VERSION 5.8 ;
BUSBITCHARS "[]" ;
DIVIDERCHAR "/" ;
UNITS
    DATABASE MICRONS 1000 ;
END UNITS

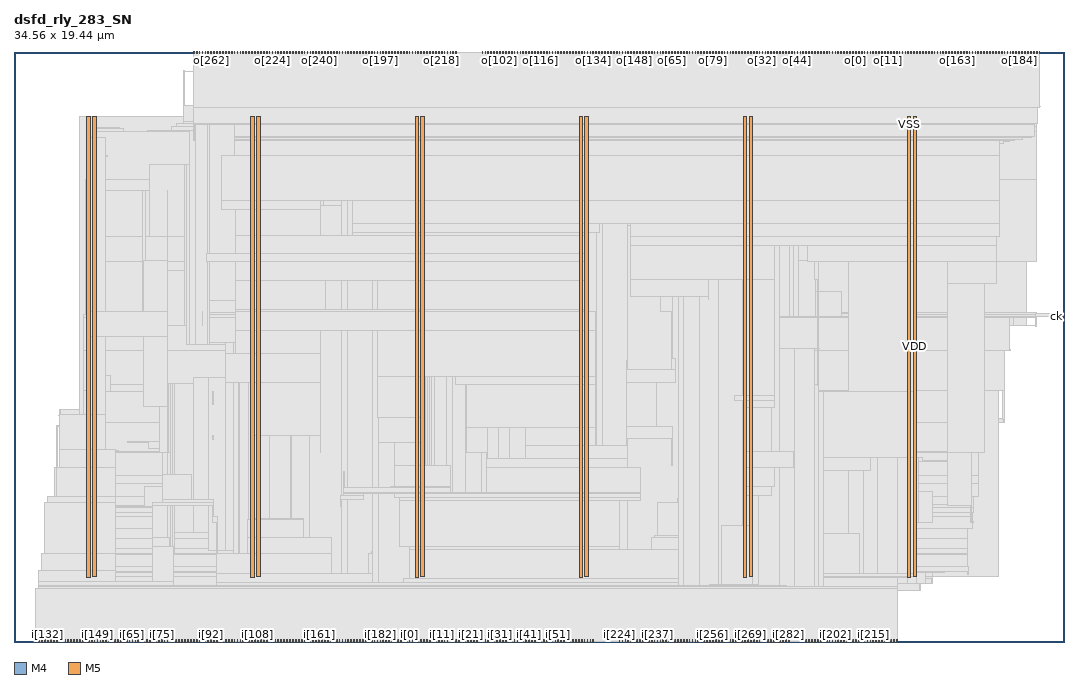
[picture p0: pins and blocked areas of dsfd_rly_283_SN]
MACRO dsfd_rly_283_SN
  FOREIGN dsfd_rly_283_SN 0 0 ;
  CLASS BLOCK ;
  SIZE 34.56 BY 19.44 ;
  PIN ck
    DIRECTION INPUT ;
    USE SIGNAL ;
    PORT
      LAYER M4 ;
        RECT  34.476 10.704 34.56 10.728 ;
    END
  END ck
  PIN i[0]
    DIRECTION INPUT ;
    USE SIGNAL ;
    PORT
      LAYER M5 ;
        RECT  13.008 0 13.032 0.084 ;
    END
  END i[0]
  PIN i[100]
    DIRECTION INPUT ;
    USE SIGNAL ;
    PORT
      LAYER M5 ;
        RECT  7.248 0 7.272 0.084 ;
    END
  END i[100]
  PIN i[101]
    DIRECTION INPUT ;
    USE SIGNAL ;
    PORT
      LAYER M5 ;
        RECT  7.344 0 7.368 0.084 ;
    END
  END i[101]
  PIN i[102]
    DIRECTION INPUT ;
    USE SIGNAL ;
    PORT
      LAYER M5 ;
        RECT  7.44 0 7.464 0.084 ;
    END
  END i[102]
  PIN i[103]
    DIRECTION INPUT ;
    USE SIGNAL ;
    PORT
      LAYER M5 ;
        RECT  7.536 0 7.56 0.084 ;
    END
  END i[103]
  PIN i[104]
    DIRECTION INPUT ;
    USE SIGNAL ;
    PORT
      LAYER M5 ;
        RECT  7.632 0 7.656 0.084 ;
    END
  END i[104]
  PIN i[105]
    DIRECTION INPUT ;
    USE SIGNAL ;
    PORT
      LAYER M5 ;
        RECT  7.728 0 7.752 0.084 ;
    END
  END i[105]
  PIN i[106]
    DIRECTION INPUT ;
    USE SIGNAL ;
    PORT
      LAYER M5 ;
        RECT  7.824 0 7.848 0.084 ;
    END
  END i[106]
  PIN i[107]
    DIRECTION INPUT ;
    USE SIGNAL ;
    PORT
      LAYER M5 ;
        RECT  7.92 0 7.944 0.084 ;
    END
  END i[107]
  PIN i[108]
    DIRECTION INPUT ;
    USE SIGNAL ;
    PORT
      LAYER M5 ;
        RECT  8.016 0 8.04 0.084 ;
    END
  END i[108]
  PIN i[109]
    DIRECTION INPUT ;
    USE SIGNAL ;
    PORT
      LAYER M5 ;
        RECT  8.112 0 8.136 0.084 ;
    END
  END i[109]
  PIN i[10]
    DIRECTION INPUT ;
    USE SIGNAL ;
    PORT
      LAYER M5 ;
        RECT  13.968 0 13.992 0.084 ;
    END
  END i[10]
  PIN i[110]
    DIRECTION INPUT ;
    USE SIGNAL ;
    PORT
      LAYER M5 ;
        RECT  8.208 0 8.232 0.084 ;
    END
  END i[110]
  PIN i[111]
    DIRECTION INPUT ;
    USE SIGNAL ;
    PORT
      LAYER M5 ;
        RECT  8.304 0 8.328 0.084 ;
    END
  END i[111]
  PIN i[112]
    DIRECTION INPUT ;
    USE SIGNAL ;
    PORT
      LAYER M5 ;
        RECT  8.4 0 8.424 0.084 ;
    END
  END i[112]
  PIN i[113]
    DIRECTION INPUT ;
    USE SIGNAL ;
    PORT
      LAYER M5 ;
        RECT  8.496 0 8.52 0.084 ;
    END
  END i[113]
  PIN i[114]
    DIRECTION INPUT ;
    USE SIGNAL ;
    PORT
      LAYER M5 ;
        RECT  8.592 0 8.616 0.084 ;
    END
  END i[114]
  PIN i[115]
    DIRECTION INPUT ;
    USE SIGNAL ;
    PORT
      LAYER M5 ;
        RECT  8.688 0 8.712 0.084 ;
    END
  END i[115]
  PIN i[116]
    DIRECTION INPUT ;
    USE SIGNAL ;
    PORT
      LAYER M5 ;
        RECT  8.784 0 8.808 0.084 ;
    END
  END i[116]
  PIN i[117]
    DIRECTION INPUT ;
    USE SIGNAL ;
    PORT
      LAYER M5 ;
        RECT  8.88 0 8.904 0.084 ;
    END
  END i[117]
  PIN i[118]
    DIRECTION INPUT ;
    USE SIGNAL ;
    PORT
      LAYER M5 ;
        RECT  8.976 0 9 0.084 ;
    END
  END i[118]
  PIN i[119]
    DIRECTION INPUT ;
    USE SIGNAL ;
    PORT
      LAYER M5 ;
        RECT  9.072 0 9.096 0.084 ;
    END
  END i[119]
  PIN i[11]
    DIRECTION INPUT ;
    USE SIGNAL ;
    PORT
      LAYER M5 ;
        RECT  14.064 0 14.088 0.084 ;
    END
  END i[11]
  PIN i[120]
    DIRECTION INPUT ;
    USE SIGNAL ;
    PORT
      LAYER M5 ;
        RECT  9.168 0 9.192 0.084 ;
    END
  END i[120]
  PIN i[121]
    DIRECTION INPUT ;
    USE SIGNAL ;
    PORT
      LAYER M5 ;
        RECT  9.264 0 9.288 0.084 ;
    END
  END i[121]
  PIN i[122]
    DIRECTION INPUT ;
    USE SIGNAL ;
    PORT
      LAYER M5 ;
        RECT  9.36 0 9.384 0.084 ;
    END
  END i[122]
  PIN i[123]
    DIRECTION INPUT ;
    USE SIGNAL ;
    PORT
      LAYER M5 ;
        RECT  9.456 0 9.48 0.084 ;
    END
  END i[123]
  PIN i[124]
    DIRECTION INPUT ;
    USE SIGNAL ;
    PORT
      LAYER M5 ;
        RECT  9.552 0 9.576 0.084 ;
    END
  END i[124]
  PIN i[125]
    DIRECTION INPUT ;
    USE SIGNAL ;
    PORT
      LAYER M5 ;
        RECT  9.648 0 9.672 0.084 ;
    END
  END i[125]
  PIN i[126]
    DIRECTION INPUT ;
    USE SIGNAL ;
    PORT
      LAYER M5 ;
        RECT  9.744 0 9.768 0.084 ;
    END
  END i[126]
  PIN i[127]
    DIRECTION INPUT ;
    USE SIGNAL ;
    PORT
      LAYER M5 ;
        RECT  9.84 0 9.864 0.084 ;
    END
  END i[127]
  PIN i[128]
    DIRECTION INPUT ;
    USE SIGNAL ;
    PORT
      LAYER M5 ;
        RECT  0.72 0 0.744 0.084 ;
    END
  END i[128]
  PIN i[129]
    DIRECTION INPUT ;
    USE SIGNAL ;
    PORT
      LAYER M5 ;
        RECT  0.816 0 0.84 0.084 ;
    END
  END i[129]
  PIN i[12]
    DIRECTION INPUT ;
    USE SIGNAL ;
    PORT
      LAYER M5 ;
        RECT  14.16 0 14.184 0.084 ;
    END
  END i[12]
  PIN i[130]
    DIRECTION INPUT ;
    USE SIGNAL ;
    PORT
      LAYER M5 ;
        RECT  0.912 0 0.936 0.084 ;
    END
  END i[130]
  PIN i[131]
    DIRECTION INPUT ;
    USE SIGNAL ;
    PORT
      LAYER M5 ;
        RECT  1.008 0 1.032 0.084 ;
    END
  END i[131]
  PIN i[132]
    DIRECTION INPUT ;
    USE SIGNAL ;
    PORT
      LAYER M5 ;
        RECT  1.104 0 1.128 0.084 ;
    END
  END i[132]
  PIN i[133]
    DIRECTION INPUT ;
    USE SIGNAL ;
    PORT
      LAYER M5 ;
        RECT  1.2 0 1.224 0.084 ;
    END
  END i[133]
  PIN i[134]
    DIRECTION INPUT ;
    USE SIGNAL ;
    PORT
      LAYER M5 ;
        RECT  1.296 0 1.32 0.084 ;
    END
  END i[134]
  PIN i[135]
    DIRECTION INPUT ;
    USE SIGNAL ;
    PORT
      LAYER M5 ;
        RECT  1.392 0 1.416 0.084 ;
    END
  END i[135]
  PIN i[136]
    DIRECTION INPUT ;
    USE SIGNAL ;
    PORT
      LAYER M5 ;
        RECT  1.488 0 1.512 0.084 ;
    END
  END i[136]
  PIN i[137]
    DIRECTION INPUT ;
    USE SIGNAL ;
    PORT
      LAYER M5 ;
        RECT  1.584 0 1.608 0.084 ;
    END
  END i[137]
  PIN i[138]
    DIRECTION INPUT ;
    USE SIGNAL ;
    PORT
      LAYER M5 ;
        RECT  1.68 0 1.704 0.084 ;
    END
  END i[138]
  PIN i[139]
    DIRECTION INPUT ;
    USE SIGNAL ;
    PORT
      LAYER M5 ;
        RECT  1.776 0 1.8 0.084 ;
    END
  END i[139]
  PIN i[13]
    DIRECTION INPUT ;
    USE SIGNAL ;
    PORT
      LAYER M5 ;
        RECT  14.256 0 14.28 0.084 ;
    END
  END i[13]
  PIN i[140]
    DIRECTION INPUT ;
    USE SIGNAL ;
    PORT
      LAYER M5 ;
        RECT  1.872 0 1.896 0.084 ;
    END
  END i[140]
  PIN i[141]
    DIRECTION INPUT ;
    USE SIGNAL ;
    PORT
      LAYER M5 ;
        RECT  1.968 0 1.992 0.084 ;
    END
  END i[141]
  PIN i[142]
    DIRECTION INPUT ;
    USE SIGNAL ;
    PORT
      LAYER M5 ;
        RECT  2.064 0 2.088 0.084 ;
    END
  END i[142]
  PIN i[143]
    DIRECTION INPUT ;
    USE SIGNAL ;
    PORT
      LAYER M5 ;
        RECT  2.16 0 2.184 0.084 ;
    END
  END i[143]
  PIN i[144]
    DIRECTION INPUT ;
    USE SIGNAL ;
    PORT
      LAYER M5 ;
        RECT  2.256 0 2.28 0.084 ;
    END
  END i[144]
  PIN i[145]
    DIRECTION INPUT ;
    USE SIGNAL ;
    PORT
      LAYER M5 ;
        RECT  2.352 0 2.376 0.084 ;
    END
  END i[145]
  PIN i[146]
    DIRECTION INPUT ;
    USE SIGNAL ;
    PORT
      LAYER M5 ;
        RECT  2.448 0 2.472 0.084 ;
    END
  END i[146]
  PIN i[147]
    DIRECTION INPUT ;
    USE SIGNAL ;
    PORT
      LAYER M5 ;
        RECT  2.544 0 2.568 0.084 ;
    END
  END i[147]
  PIN i[148]
    DIRECTION INPUT ;
    USE SIGNAL ;
    PORT
      LAYER M5 ;
        RECT  2.64 0 2.664 0.084 ;
    END
  END i[148]
  PIN i[149]
    DIRECTION INPUT ;
    USE SIGNAL ;
    PORT
      LAYER M5 ;
        RECT  2.736 0 2.76 0.084 ;
    END
  END i[149]
  PIN i[14]
    DIRECTION INPUT ;
    USE SIGNAL ;
    PORT
      LAYER M5 ;
        RECT  14.352 0 14.376 0.084 ;
    END
  END i[14]
  PIN i[150]
    DIRECTION INPUT ;
    USE SIGNAL ;
    PORT
      LAYER M5 ;
        RECT  2.832 0 2.856 0.084 ;
    END
  END i[150]
  PIN i[151]
    DIRECTION INPUT ;
    USE SIGNAL ;
    PORT
      LAYER M5 ;
        RECT  2.928 0 2.952 0.084 ;
    END
  END i[151]
  PIN i[152]
    DIRECTION INPUT ;
    USE SIGNAL ;
    PORT
      LAYER M5 ;
        RECT  3.024 0 3.048 0.084 ;
    END
  END i[152]
  PIN i[153]
    DIRECTION INPUT ;
    USE SIGNAL ;
    PORT
      LAYER M5 ;
        RECT  3.12 0 3.144 0.084 ;
    END
  END i[153]
  PIN i[154]
    DIRECTION INPUT ;
    USE SIGNAL ;
    PORT
      LAYER M5 ;
        RECT  3.216 0 3.24 0.084 ;
    END
  END i[154]
  PIN i[155]
    DIRECTION INPUT ;
    USE SIGNAL ;
    PORT
      LAYER M5 ;
        RECT  3.312 0 3.336 0.084 ;
    END
  END i[155]
  PIN i[156]
    DIRECTION INPUT ;
    USE SIGNAL ;
    PORT
      LAYER M5 ;
        RECT  3.408 0 3.432 0.084 ;
    END
  END i[156]
  PIN i[157]
    DIRECTION INPUT ;
    USE SIGNAL ;
    PORT
      LAYER M5 ;
        RECT  3.504 0 3.528 0.084 ;
    END
  END i[157]
  PIN i[158]
    DIRECTION INPUT ;
    USE SIGNAL ;
    PORT
      LAYER M5 ;
        RECT  3.6 0 3.624 0.084 ;
    END
  END i[158]
  PIN i[159]
    DIRECTION INPUT ;
    USE SIGNAL ;
    PORT
      LAYER M5 ;
        RECT  3.696 0 3.72 0.084 ;
    END
  END i[159]
  PIN i[15]
    DIRECTION INPUT ;
    USE SIGNAL ;
    PORT
      LAYER M5 ;
        RECT  14.448 0 14.472 0.084 ;
    END
  END i[15]
  PIN i[160]
    DIRECTION INPUT ;
    USE SIGNAL ;
    PORT
      LAYER M5 ;
        RECT  9.936 0 9.96 0.084 ;
    END
  END i[160]
  PIN i[161]
    DIRECTION INPUT ;
    USE SIGNAL ;
    PORT
      LAYER M5 ;
        RECT  10.032 0 10.056 0.084 ;
    END
  END i[161]
  PIN i[162]
    DIRECTION INPUT ;
    USE SIGNAL ;
    PORT
      LAYER M5 ;
        RECT  10.128 0 10.152 0.084 ;
    END
  END i[162]
  PIN i[163]
    DIRECTION INPUT ;
    USE SIGNAL ;
    PORT
      LAYER M5 ;
        RECT  10.224 0 10.248 0.084 ;
    END
  END i[163]
  PIN i[164]
    DIRECTION INPUT ;
    USE SIGNAL ;
    PORT
      LAYER M5 ;
        RECT  10.32 0 10.344 0.084 ;
    END
  END i[164]
  PIN i[165]
    DIRECTION INPUT ;
    USE SIGNAL ;
    PORT
      LAYER M5 ;
        RECT  10.416 0 10.44 0.084 ;
    END
  END i[165]
  PIN i[166]
    DIRECTION INPUT ;
    USE SIGNAL ;
    PORT
      LAYER M5 ;
        RECT  10.512 0 10.536 0.084 ;
    END
  END i[166]
  PIN i[167]
    DIRECTION INPUT ;
    USE SIGNAL ;
    PORT
      LAYER M5 ;
        RECT  10.608 0 10.632 0.084 ;
    END
  END i[167]
  PIN i[168]
    DIRECTION INPUT ;
    USE SIGNAL ;
    PORT
      LAYER M5 ;
        RECT  10.704 0 10.728 0.084 ;
    END
  END i[168]
  PIN i[169]
    DIRECTION INPUT ;
    USE SIGNAL ;
    PORT
      LAYER M5 ;
        RECT  10.8 0 10.824 0.084 ;
    END
  END i[169]
  PIN i[16]
    DIRECTION INPUT ;
    USE SIGNAL ;
    PORT
      LAYER M5 ;
        RECT  14.544 0 14.568 0.084 ;
    END
  END i[16]
  PIN i[170]
    DIRECTION INPUT ;
    USE SIGNAL ;
    PORT
      LAYER M5 ;
        RECT  10.896 0 10.92 0.084 ;
    END
  END i[170]
  PIN i[171]
    DIRECTION INPUT ;
    USE SIGNAL ;
    PORT
      LAYER M5 ;
        RECT  10.992 0 11.016 0.084 ;
    END
  END i[171]
  PIN i[172]
    DIRECTION INPUT ;
    USE SIGNAL ;
    PORT
      LAYER M5 ;
        RECT  11.088 0 11.112 0.084 ;
    END
  END i[172]
  PIN i[173]
    DIRECTION INPUT ;
    USE SIGNAL ;
    PORT
      LAYER M5 ;
        RECT  11.184 0 11.208 0.084 ;
    END
  END i[173]
  PIN i[174]
    DIRECTION INPUT ;
    USE SIGNAL ;
    PORT
      LAYER M5 ;
        RECT  11.28 0 11.304 0.084 ;
    END
  END i[174]
  PIN i[175]
    DIRECTION INPUT ;
    USE SIGNAL ;
    PORT
      LAYER M5 ;
        RECT  11.376 0 11.4 0.084 ;
    END
  END i[175]
  PIN i[176]
    DIRECTION INPUT ;
    USE SIGNAL ;
    PORT
      LAYER M5 ;
        RECT  11.472 0 11.496 0.084 ;
    END
  END i[176]
  PIN i[177]
    DIRECTION INPUT ;
    USE SIGNAL ;
    PORT
      LAYER M5 ;
        RECT  11.568 0 11.592 0.084 ;
    END
  END i[177]
  PIN i[178]
    DIRECTION INPUT ;
    USE SIGNAL ;
    PORT
      LAYER M5 ;
        RECT  11.664 0 11.688 0.084 ;
    END
  END i[178]
  PIN i[179]
    DIRECTION INPUT ;
    USE SIGNAL ;
    PORT
      LAYER M5 ;
        RECT  11.76 0 11.784 0.084 ;
    END
  END i[179]
  PIN i[17]
    DIRECTION INPUT ;
    USE SIGNAL ;
    PORT
      LAYER M5 ;
        RECT  14.64 0 14.664 0.084 ;
    END
  END i[17]
  PIN i[180]
    DIRECTION INPUT ;
    USE SIGNAL ;
    PORT
      LAYER M5 ;
        RECT  11.856 0 11.88 0.084 ;
    END
  END i[180]
  PIN i[181]
    DIRECTION INPUT ;
    USE SIGNAL ;
    PORT
      LAYER M5 ;
        RECT  11.952 0 11.976 0.084 ;
    END
  END i[181]
  PIN i[182]
    DIRECTION INPUT ;
    USE SIGNAL ;
    PORT
      LAYER M5 ;
        RECT  12.048 0 12.072 0.084 ;
    END
  END i[182]
  PIN i[183]
    DIRECTION INPUT ;
    USE SIGNAL ;
    PORT
      LAYER M5 ;
        RECT  12.144 0 12.168 0.084 ;
    END
  END i[183]
  PIN i[184]
    DIRECTION INPUT ;
    USE SIGNAL ;
    PORT
      LAYER M5 ;
        RECT  12.24 0 12.264 0.084 ;
    END
  END i[184]
  PIN i[185]
    DIRECTION INPUT ;
    USE SIGNAL ;
    PORT
      LAYER M5 ;
        RECT  12.336 0 12.36 0.084 ;
    END
  END i[185]
  PIN i[186]
    DIRECTION INPUT ;
    USE SIGNAL ;
    PORT
      LAYER M5 ;
        RECT  12.432 0 12.456 0.084 ;
    END
  END i[186]
  PIN i[187]
    DIRECTION INPUT ;
    USE SIGNAL ;
    PORT
      LAYER M5 ;
        RECT  12.528 0 12.552 0.084 ;
    END
  END i[187]
  PIN i[188]
    DIRECTION INPUT ;
    USE SIGNAL ;
    PORT
      LAYER M5 ;
        RECT  12.624 0 12.648 0.084 ;
    END
  END i[188]
  PIN i[189]
    DIRECTION INPUT ;
    USE SIGNAL ;
    PORT
      LAYER M5 ;
        RECT  12.72 0 12.744 0.084 ;
    END
  END i[189]
  PIN i[18]
    DIRECTION INPUT ;
    USE SIGNAL ;
    PORT
      LAYER M5 ;
        RECT  14.736 0 14.76 0.084 ;
    END
  END i[18]
  PIN i[190]
    DIRECTION INPUT ;
    USE SIGNAL ;
    PORT
      LAYER M5 ;
        RECT  12.816 0 12.84 0.084 ;
    END
  END i[190]
  PIN i[191]
    DIRECTION INPUT ;
    USE SIGNAL ;
    PORT
      LAYER M5 ;
        RECT  12.912 0 12.936 0.084 ;
    END
  END i[191]
  PIN i[192]
    DIRECTION INPUT ;
    USE SIGNAL ;
    PORT
      LAYER M5 ;
        RECT  26.064 0 26.088 0.084 ;
    END
  END i[192]
  PIN i[193]
    DIRECTION INPUT ;
    USE SIGNAL ;
    PORT
      LAYER M5 ;
        RECT  26.16 0 26.184 0.084 ;
    END
  END i[193]
  PIN i[194]
    DIRECTION INPUT ;
    USE SIGNAL ;
    PORT
      LAYER M5 ;
        RECT  26.256 0 26.28 0.084 ;
    END
  END i[194]
  PIN i[195]
    DIRECTION INPUT ;
    USE SIGNAL ;
    PORT
      LAYER M5 ;
        RECT  26.352 0 26.376 0.084 ;
    END
  END i[195]
  PIN i[196]
    DIRECTION INPUT ;
    USE SIGNAL ;
    PORT
      LAYER M5 ;
        RECT  26.448 0 26.472 0.084 ;
    END
  END i[196]
  PIN i[197]
    DIRECTION INPUT ;
    USE SIGNAL ;
    PORT
      LAYER M5 ;
        RECT  26.544 0 26.568 0.084 ;
    END
  END i[197]
  PIN i[198]
    DIRECTION INPUT ;
    USE SIGNAL ;
    PORT
      LAYER M5 ;
        RECT  26.64 0 26.664 0.084 ;
    END
  END i[198]
  PIN i[199]
    DIRECTION INPUT ;
    USE SIGNAL ;
    PORT
      LAYER M5 ;
        RECT  26.736 0 26.76 0.084 ;
    END
  END i[199]
  PIN i[19]
    DIRECTION INPUT ;
    USE SIGNAL ;
    PORT
      LAYER M5 ;
        RECT  14.832 0 14.856 0.084 ;
    END
  END i[19]
  PIN i[1]
    DIRECTION INPUT ;
    USE SIGNAL ;
    PORT
      LAYER M5 ;
        RECT  13.104 0 13.128 0.084 ;
    END
  END i[1]
  PIN i[200]
    DIRECTION INPUT ;
    USE SIGNAL ;
    PORT
      LAYER M5 ;
        RECT  26.832 0 26.856 0.084 ;
    END
  END i[200]
  PIN i[201]
    DIRECTION INPUT ;
    USE SIGNAL ;
    PORT
      LAYER M5 ;
        RECT  26.928 0 26.952 0.084 ;
    END
  END i[201]
  PIN i[202]
    DIRECTION INPUT ;
    USE SIGNAL ;
    PORT
      LAYER M5 ;
        RECT  27.024 0 27.048 0.084 ;
    END
  END i[202]
  PIN i[203]
    DIRECTION INPUT ;
    USE SIGNAL ;
    PORT
      LAYER M5 ;
        RECT  27.12 0 27.144 0.084 ;
    END
  END i[203]
  PIN i[204]
    DIRECTION INPUT ;
    USE SIGNAL ;
    PORT
      LAYER M5 ;
        RECT  27.216 0 27.24 0.084 ;
    END
  END i[204]
  PIN i[205]
    DIRECTION INPUT ;
    USE SIGNAL ;
    PORT
      LAYER M5 ;
        RECT  27.312 0 27.336 0.084 ;
    END
  END i[205]
  PIN i[206]
    DIRECTION INPUT ;
    USE SIGNAL ;
    PORT
      LAYER M5 ;
        RECT  27.408 0 27.432 0.084 ;
    END
  END i[206]
  PIN i[207]
    DIRECTION INPUT ;
    USE SIGNAL ;
    PORT
      LAYER M5 ;
        RECT  27.504 0 27.528 0.084 ;
    END
  END i[207]
  PIN i[208]
    DIRECTION INPUT ;
    USE SIGNAL ;
    PORT
      LAYER M5 ;
        RECT  27.6 0 27.624 0.084 ;
    END
  END i[208]
  PIN i[209]
    DIRECTION INPUT ;
    USE SIGNAL ;
    PORT
      LAYER M5 ;
        RECT  27.696 0 27.72 0.084 ;
    END
  END i[209]
  PIN i[20]
    DIRECTION INPUT ;
    USE SIGNAL ;
    PORT
      LAYER M5 ;
        RECT  14.928 0 14.952 0.084 ;
    END
  END i[20]
  PIN i[210]
    DIRECTION INPUT ;
    USE SIGNAL ;
    PORT
      LAYER M5 ;
        RECT  27.792 0 27.816 0.084 ;
    END
  END i[210]
  PIN i[211]
    DIRECTION INPUT ;
    USE SIGNAL ;
    PORT
      LAYER M5 ;
        RECT  27.888 0 27.912 0.084 ;
    END
  END i[211]
  PIN i[212]
    DIRECTION INPUT ;
    USE SIGNAL ;
    PORT
      LAYER M5 ;
        RECT  27.984 0 28.008 0.084 ;
    END
  END i[212]
  PIN i[213]
    DIRECTION INPUT ;
    USE SIGNAL ;
    PORT
      LAYER M5 ;
        RECT  28.08 0 28.104 0.084 ;
    END
  END i[213]
  PIN i[214]
    DIRECTION INPUT ;
    USE SIGNAL ;
    PORT
      LAYER M5 ;
        RECT  28.176 0 28.2 0.084 ;
    END
  END i[214]
  PIN i[215]
    DIRECTION INPUT ;
    USE SIGNAL ;
    PORT
      LAYER M5 ;
        RECT  28.272 0 28.296 0.084 ;
    END
  END i[215]
  PIN i[216]
    DIRECTION INPUT ;
    USE SIGNAL ;
    PORT
      LAYER M5 ;
        RECT  28.368 0 28.392 0.084 ;
    END
  END i[216]
  PIN i[217]
    DIRECTION INPUT ;
    USE SIGNAL ;
    PORT
      LAYER M5 ;
        RECT  28.464 0 28.488 0.084 ;
    END
  END i[217]
  PIN i[218]
    DIRECTION INPUT ;
    USE SIGNAL ;
    PORT
      LAYER M5 ;
        RECT  28.56 0 28.584 0.084 ;
    END
  END i[218]
  PIN i[219]
    DIRECTION INPUT ;
    USE SIGNAL ;
    PORT
      LAYER M5 ;
        RECT  28.656 0 28.68 0.084 ;
    END
  END i[219]
  PIN i[21]
    DIRECTION INPUT ;
    USE SIGNAL ;
    PORT
      LAYER M5 ;
        RECT  15.024 0 15.048 0.084 ;
    END
  END i[21]
  PIN i[220]
    DIRECTION INPUT ;
    USE SIGNAL ;
    PORT
      LAYER M5 ;
        RECT  28.752 0 28.776 0.084 ;
    END
  END i[220]
  PIN i[221]
    DIRECTION INPUT ;
    USE SIGNAL ;
    PORT
      LAYER M5 ;
        RECT  28.848 0 28.872 0.084 ;
    END
  END i[221]
  PIN i[222]
    DIRECTION INPUT ;
    USE SIGNAL ;
    PORT
      LAYER M5 ;
        RECT  28.944 0 28.968 0.084 ;
    END
  END i[222]
  PIN i[223]
    DIRECTION INPUT ;
    USE SIGNAL ;
    PORT
      LAYER M5 ;
        RECT  29.04 0 29.064 0.084 ;
    END
  END i[223]
  PIN i[224]
    DIRECTION INPUT ;
    USE SIGNAL ;
    PORT
      LAYER M5 ;
        RECT  19.92 0 19.944 0.084 ;
    END
  END i[224]
  PIN i[225]
    DIRECTION INPUT ;
    USE SIGNAL ;
    PORT
      LAYER M5 ;
        RECT  20.016 0 20.04 0.084 ;
    END
  END i[225]
  PIN i[226]
    DIRECTION INPUT ;
    USE SIGNAL ;
    PORT
      LAYER M5 ;
        RECT  20.112 0 20.136 0.084 ;
    END
  END i[226]
  PIN i[227]
    DIRECTION INPUT ;
    USE SIGNAL ;
    PORT
      LAYER M5 ;
        RECT  20.208 0 20.232 0.084 ;
    END
  END i[227]
  PIN i[228]
    DIRECTION INPUT ;
    USE SIGNAL ;
    PORT
      LAYER M5 ;
        RECT  20.304 0 20.328 0.084 ;
    END
  END i[228]
  PIN i[229]
    DIRECTION INPUT ;
    USE SIGNAL ;
    PORT
      LAYER M5 ;
        RECT  20.4 0 20.424 0.084 ;
    END
  END i[229]
  PIN i[22]
    DIRECTION INPUT ;
    USE SIGNAL ;
    PORT
      LAYER M5 ;
        RECT  15.12 0 15.144 0.084 ;
    END
  END i[22]
  PIN i[230]
    DIRECTION INPUT ;
    USE SIGNAL ;
    PORT
      LAYER M5 ;
        RECT  20.496 0 20.52 0.084 ;
    END
  END i[230]
  PIN i[231]
    DIRECTION INPUT ;
    USE SIGNAL ;
    PORT
      LAYER M5 ;
        RECT  20.592 0 20.616 0.084 ;
    END
  END i[231]
  PIN i[232]
    DIRECTION INPUT ;
    USE SIGNAL ;
    PORT
      LAYER M5 ;
        RECT  20.688 0 20.712 0.084 ;
    END
  END i[232]
  PIN i[233]
    DIRECTION INPUT ;
    USE SIGNAL ;
    PORT
      LAYER M5 ;
        RECT  20.784 0 20.808 0.084 ;
    END
  END i[233]
  PIN i[234]
    DIRECTION INPUT ;
    USE SIGNAL ;
    PORT
      LAYER M5 ;
        RECT  20.88 0 20.904 0.084 ;
    END
  END i[234]
  PIN i[235]
    DIRECTION INPUT ;
    USE SIGNAL ;
    PORT
      LAYER M5 ;
        RECT  20.976 0 21 0.084 ;
    END
  END i[235]
  PIN i[236]
    DIRECTION INPUT ;
    USE SIGNAL ;
    PORT
      LAYER M5 ;
        RECT  21.072 0 21.096 0.084 ;
    END
  END i[236]
  PIN i[237]
    DIRECTION INPUT ;
    USE SIGNAL ;
    PORT
      LAYER M5 ;
        RECT  21.168 0 21.192 0.084 ;
    END
  END i[237]
  PIN i[238]
    DIRECTION INPUT ;
    USE SIGNAL ;
    PORT
      LAYER M5 ;
        RECT  21.264 0 21.288 0.084 ;
    END
  END i[238]
  PIN i[239]
    DIRECTION INPUT ;
    USE SIGNAL ;
    PORT
      LAYER M5 ;
        RECT  21.36 0 21.384 0.084 ;
    END
  END i[239]
  PIN i[23]
    DIRECTION INPUT ;
    USE SIGNAL ;
    PORT
      LAYER M5 ;
        RECT  15.216 0 15.24 0.084 ;
    END
  END i[23]
  PIN i[240]
    DIRECTION INPUT ;
    USE SIGNAL ;
    PORT
      LAYER M5 ;
        RECT  21.456 0 21.48 0.084 ;
    END
  END i[240]
  PIN i[241]
    DIRECTION INPUT ;
    USE SIGNAL ;
    PORT
      LAYER M5 ;
        RECT  21.552 0 21.576 0.084 ;
    END
  END i[241]
  PIN i[242]
    DIRECTION INPUT ;
    USE SIGNAL ;
    PORT
      LAYER M5 ;
        RECT  21.648 0 21.672 0.084 ;
    END
  END i[242]
  PIN i[243]
    DIRECTION INPUT ;
    USE SIGNAL ;
    PORT
      LAYER M5 ;
        RECT  21.744 0 21.768 0.084 ;
    END
  END i[243]
  PIN i[244]
    DIRECTION INPUT ;
    USE SIGNAL ;
    PORT
      LAYER M5 ;
        RECT  21.84 0 21.864 0.084 ;
    END
  END i[244]
  PIN i[245]
    DIRECTION INPUT ;
    USE SIGNAL ;
    PORT
      LAYER M5 ;
        RECT  21.936 0 21.96 0.084 ;
    END
  END i[245]
  PIN i[246]
    DIRECTION INPUT ;
    USE SIGNAL ;
    PORT
      LAYER M5 ;
        RECT  22.032 0 22.056 0.084 ;
    END
  END i[246]
  PIN i[247]
    DIRECTION INPUT ;
    USE SIGNAL ;
    PORT
      LAYER M5 ;
        RECT  22.128 0 22.152 0.084 ;
    END
  END i[247]
  PIN i[248]
    DIRECTION INPUT ;
    USE SIGNAL ;
    PORT
      LAYER M5 ;
        RECT  22.224 0 22.248 0.084 ;
    END
  END i[248]
  PIN i[249]
    DIRECTION INPUT ;
    USE SIGNAL ;
    PORT
      LAYER M5 ;
        RECT  22.32 0 22.344 0.084 ;
    END
  END i[249]
  PIN i[24]
    DIRECTION INPUT ;
    USE SIGNAL ;
    PORT
      LAYER M5 ;
        RECT  15.312 0 15.336 0.084 ;
    END
  END i[24]
  PIN i[250]
    DIRECTION INPUT ;
    USE SIGNAL ;
    PORT
      LAYER M5 ;
        RECT  22.416 0 22.44 0.084 ;
    END
  END i[250]
  PIN i[251]
    DIRECTION INPUT ;
    USE SIGNAL ;
    PORT
      LAYER M5 ;
        RECT  22.512 0 22.536 0.084 ;
    END
  END i[251]
  PIN i[252]
    DIRECTION INPUT ;
    USE SIGNAL ;
    PORT
      LAYER M5 ;
        RECT  22.608 0 22.632 0.084 ;
    END
  END i[252]
  PIN i[253]
    DIRECTION INPUT ;
    USE SIGNAL ;
    PORT
      LAYER M5 ;
        RECT  22.704 0 22.728 0.084 ;
    END
  END i[253]
  PIN i[254]
    DIRECTION INPUT ;
    USE SIGNAL ;
    PORT
      LAYER M5 ;
        RECT  22.8 0 22.824 0.084 ;
    END
  END i[254]
  PIN i[255]
    DIRECTION INPUT ;
    USE SIGNAL ;
    PORT
      LAYER M5 ;
        RECT  22.896 0 22.92 0.084 ;
    END
  END i[255]
  PIN i[256]
    DIRECTION INPUT ;
    USE SIGNAL ;
    PORT
      LAYER M5 ;
        RECT  22.992 0 23.016 0.084 ;
    END
  END i[256]
  PIN i[257]
    DIRECTION INPUT ;
    USE SIGNAL ;
    PORT
      LAYER M5 ;
        RECT  23.088 0 23.112 0.084 ;
    END
  END i[257]
  PIN i[258]
    DIRECTION INPUT ;
    USE SIGNAL ;
    PORT
      LAYER M5 ;
        RECT  23.184 0 23.208 0.084 ;
    END
  END i[258]
  PIN i[259]
    DIRECTION INPUT ;
    USE SIGNAL ;
    PORT
      LAYER M5 ;
        RECT  23.28 0 23.304 0.084 ;
    END
  END i[259]
  PIN i[25]
    DIRECTION INPUT ;
    USE SIGNAL ;
    PORT
      LAYER M5 ;
        RECT  15.408 0 15.432 0.084 ;
    END
  END i[25]
  PIN i[260]
    DIRECTION INPUT ;
    USE SIGNAL ;
    PORT
      LAYER M5 ;
        RECT  23.376 0 23.4 0.084 ;
    END
  END i[260]
  PIN i[261]
    DIRECTION INPUT ;
    USE SIGNAL ;
    PORT
      LAYER M5 ;
        RECT  23.472 0 23.496 0.084 ;
    END
  END i[261]
  PIN i[262]
    DIRECTION INPUT ;
    USE SIGNAL ;
    PORT
      LAYER M5 ;
        RECT  23.568 0 23.592 0.084 ;
    END
  END i[262]
  PIN i[263]
    DIRECTION INPUT ;
    USE SIGNAL ;
    PORT
      LAYER M5 ;
        RECT  23.664 0 23.688 0.084 ;
    END
  END i[263]
  PIN i[264]
    DIRECTION INPUT ;
    USE SIGNAL ;
    PORT
      LAYER M5 ;
        RECT  23.76 0 23.784 0.084 ;
    END
  END i[264]
  PIN i[265]
    DIRECTION INPUT ;
    USE SIGNAL ;
    PORT
      LAYER M5 ;
        RECT  23.856 0 23.88 0.084 ;
    END
  END i[265]
  PIN i[266]
    DIRECTION INPUT ;
    USE SIGNAL ;
    PORT
      LAYER M5 ;
        RECT  23.952 0 23.976 0.084 ;
    END
  END i[266]
  PIN i[267]
    DIRECTION INPUT ;
    USE SIGNAL ;
    PORT
      LAYER M5 ;
        RECT  24.048 0 24.072 0.084 ;
    END
  END i[267]
  PIN i[268]
    DIRECTION INPUT ;
    USE SIGNAL ;
    PORT
      LAYER M5 ;
        RECT  24.144 0 24.168 0.084 ;
    END
  END i[268]
  PIN i[269]
    DIRECTION INPUT ;
    USE SIGNAL ;
    PORT
      LAYER M5 ;
        RECT  24.24 0 24.264 0.084 ;
    END
  END i[269]
  PIN i[26]
    DIRECTION INPUT ;
    USE SIGNAL ;
    PORT
      LAYER M5 ;
        RECT  15.504 0 15.528 0.084 ;
    END
  END i[26]
  PIN i[270]
    DIRECTION INPUT ;
    USE SIGNAL ;
    PORT
      LAYER M5 ;
        RECT  24.336 0 24.36 0.084 ;
    END
  END i[270]
  PIN i[271]
    DIRECTION INPUT ;
    USE SIGNAL ;
    PORT
      LAYER M5 ;
        RECT  24.432 0 24.456 0.084 ;
    END
  END i[271]
  PIN i[272]
    DIRECTION INPUT ;
    USE SIGNAL ;
    PORT
      LAYER M5 ;
        RECT  24.528 0 24.552 0.084 ;
    END
  END i[272]
  PIN i[273]
    DIRECTION INPUT ;
    USE SIGNAL ;
    PORT
      LAYER M5 ;
        RECT  24.624 0 24.648 0.084 ;
    END
  END i[273]
  PIN i[274]
    DIRECTION INPUT ;
    USE SIGNAL ;
    PORT
      LAYER M5 ;
        RECT  24.72 0 24.744 0.084 ;
    END
  END i[274]
  PIN i[275]
    DIRECTION INPUT ;
    USE SIGNAL ;
    PORT
      LAYER M5 ;
        RECT  24.816 0 24.84 0.084 ;
    END
  END i[275]
  PIN i[276]
    DIRECTION INPUT ;
    USE SIGNAL ;
    PORT
      LAYER M5 ;
        RECT  24.912 0 24.936 0.084 ;
    END
  END i[276]
  PIN i[277]
    DIRECTION INPUT ;
    USE SIGNAL ;
    PORT
      LAYER M5 ;
        RECT  25.008 0 25.032 0.084 ;
    END
  END i[277]
  PIN i[278]
    DIRECTION INPUT ;
    USE SIGNAL ;
    PORT
      LAYER M5 ;
        RECT  25.104 0 25.128 0.084 ;
    END
  END i[278]
  PIN i[279]
    DIRECTION INPUT ;
    USE SIGNAL ;
    PORT
      LAYER M5 ;
        RECT  25.2 0 25.224 0.084 ;
    END
  END i[279]
  PIN i[27]
    DIRECTION INPUT ;
    USE SIGNAL ;
    PORT
      LAYER M5 ;
        RECT  15.6 0 15.624 0.084 ;
    END
  END i[27]
  PIN i[280]
    DIRECTION INPUT ;
    USE SIGNAL ;
    PORT
      LAYER M5 ;
        RECT  25.296 0 25.32 0.084 ;
    END
  END i[280]
  PIN i[281]
    DIRECTION INPUT ;
    USE SIGNAL ;
    PORT
      LAYER M5 ;
        RECT  25.392 0 25.416 0.084 ;
    END
  END i[281]
  PIN i[282]
    DIRECTION INPUT ;
    USE SIGNAL ;
    PORT
      LAYER M5 ;
        RECT  25.488 0 25.512 0.084 ;
    END
  END i[282]
  PIN i[28]
    DIRECTION INPUT ;
    USE SIGNAL ;
    PORT
      LAYER M5 ;
        RECT  15.696 0 15.72 0.084 ;
    END
  END i[28]
  PIN i[29]
    DIRECTION INPUT ;
    USE SIGNAL ;
    PORT
      LAYER M5 ;
        RECT  15.792 0 15.816 0.084 ;
    END
  END i[29]
  PIN i[2]
    DIRECTION INPUT ;
    USE SIGNAL ;
    PORT
      LAYER M5 ;
        RECT  13.2 0 13.224 0.084 ;
    END
  END i[2]
  PIN i[30]
    DIRECTION INPUT ;
    USE SIGNAL ;
    PORT
      LAYER M5 ;
        RECT  15.888 0 15.912 0.084 ;
    END
  END i[30]
  PIN i[31]
    DIRECTION INPUT ;
    USE SIGNAL ;
    PORT
      LAYER M5 ;
        RECT  15.984 0 16.008 0.084 ;
    END
  END i[31]
  PIN i[32]
    DIRECTION INPUT ;
    USE SIGNAL ;
    PORT
      LAYER M5 ;
        RECT  16.08 0 16.104 0.084 ;
    END
  END i[32]
  PIN i[33]
    DIRECTION INPUT ;
    USE SIGNAL ;
    PORT
      LAYER M5 ;
        RECT  16.176 0 16.2 0.084 ;
    END
  END i[33]
  PIN i[34]
    DIRECTION INPUT ;
    USE SIGNAL ;
    PORT
      LAYER M5 ;
        RECT  16.272 0 16.296 0.084 ;
    END
  END i[34]
  PIN i[35]
    DIRECTION INPUT ;
    USE SIGNAL ;
    PORT
      LAYER M5 ;
        RECT  16.368 0 16.392 0.084 ;
    END
  END i[35]
  PIN i[36]
    DIRECTION INPUT ;
    USE SIGNAL ;
    PORT
      LAYER M5 ;
        RECT  16.464 0 16.488 0.084 ;
    END
  END i[36]
  PIN i[37]
    DIRECTION INPUT ;
    USE SIGNAL ;
    PORT
      LAYER M5 ;
        RECT  16.56 0 16.584 0.084 ;
    END
  END i[37]
  PIN i[38]
    DIRECTION INPUT ;
    USE SIGNAL ;
    PORT
      LAYER M5 ;
        RECT  16.656 0 16.68 0.084 ;
    END
  END i[38]
  PIN i[39]
    DIRECTION INPUT ;
    USE SIGNAL ;
    PORT
      LAYER M5 ;
        RECT  16.752 0 16.776 0.084 ;
    END
  END i[39]
  PIN i[3]
    DIRECTION INPUT ;
    USE SIGNAL ;
    PORT
      LAYER M5 ;
        RECT  13.296 0 13.32 0.084 ;
    END
  END i[3]
  PIN i[40]
    DIRECTION INPUT ;
    USE SIGNAL ;
    PORT
      LAYER M5 ;
        RECT  16.848 0 16.872 0.084 ;
    END
  END i[40]
  PIN i[41]
    DIRECTION INPUT ;
    USE SIGNAL ;
    PORT
      LAYER M5 ;
        RECT  16.944 0 16.968 0.084 ;
    END
  END i[41]
  PIN i[42]
    DIRECTION INPUT ;
    USE SIGNAL ;
    PORT
      LAYER M5 ;
        RECT  17.04 0 17.064 0.084 ;
    END
  END i[42]
  PIN i[43]
    DIRECTION INPUT ;
    USE SIGNAL ;
    PORT
      LAYER M5 ;
        RECT  17.136 0 17.16 0.084 ;
    END
  END i[43]
  PIN i[44]
    DIRECTION INPUT ;
    USE SIGNAL ;
    PORT
      LAYER M5 ;
        RECT  17.232 0 17.256 0.084 ;
    END
  END i[44]
  PIN i[45]
    DIRECTION INPUT ;
    USE SIGNAL ;
    PORT
      LAYER M5 ;
        RECT  17.328 0 17.352 0.084 ;
    END
  END i[45]
  PIN i[46]
    DIRECTION INPUT ;
    USE SIGNAL ;
    PORT
      LAYER M5 ;
        RECT  17.424 0 17.448 0.084 ;
    END
  END i[46]
  PIN i[47]
    DIRECTION INPUT ;
    USE SIGNAL ;
    PORT
      LAYER M5 ;
        RECT  17.52 0 17.544 0.084 ;
    END
  END i[47]
  PIN i[48]
    DIRECTION INPUT ;
    USE SIGNAL ;
    PORT
      LAYER M5 ;
        RECT  17.616 0 17.64 0.084 ;
    END
  END i[48]
  PIN i[49]
    DIRECTION INPUT ;
    USE SIGNAL ;
    PORT
      LAYER M5 ;
        RECT  17.712 0 17.736 0.084 ;
    END
  END i[49]
  PIN i[4]
    DIRECTION INPUT ;
    USE SIGNAL ;
    PORT
      LAYER M5 ;
        RECT  13.392 0 13.416 0.084 ;
    END
  END i[4]
  PIN i[50]
    DIRECTION INPUT ;
    USE SIGNAL ;
    PORT
      LAYER M5 ;
        RECT  17.808 0 17.832 0.084 ;
    END
  END i[50]
  PIN i[51]
    DIRECTION INPUT ;
    USE SIGNAL ;
    PORT
      LAYER M5 ;
        RECT  17.904 0 17.928 0.084 ;
    END
  END i[51]
  PIN i[52]
    DIRECTION INPUT ;
    USE SIGNAL ;
    PORT
      LAYER M5 ;
        RECT  18 0 18.024 0.084 ;
    END
  END i[52]
  PIN i[53]
    DIRECTION INPUT ;
    USE SIGNAL ;
    PORT
      LAYER M5 ;
        RECT  18.096 0 18.12 0.084 ;
    END
  END i[53]
  PIN i[54]
    DIRECTION INPUT ;
    USE SIGNAL ;
    PORT
      LAYER M5 ;
        RECT  18.192 0 18.216 0.084 ;
    END
  END i[54]
  PIN i[55]
    DIRECTION INPUT ;
    USE SIGNAL ;
    PORT
      LAYER M5 ;
        RECT  18.288 0 18.312 0.084 ;
    END
  END i[55]
  PIN i[56]
    DIRECTION INPUT ;
    USE SIGNAL ;
    PORT
      LAYER M5 ;
        RECT  18.384 0 18.408 0.084 ;
    END
  END i[56]
  PIN i[57]
    DIRECTION INPUT ;
    USE SIGNAL ;
    PORT
      LAYER M5 ;
        RECT  18.48 0 18.504 0.084 ;
    END
  END i[57]
  PIN i[58]
    DIRECTION INPUT ;
    USE SIGNAL ;
    PORT
      LAYER M5 ;
        RECT  18.576 0 18.6 0.084 ;
    END
  END i[58]
  PIN i[59]
    DIRECTION INPUT ;
    USE SIGNAL ;
    PORT
      LAYER M5 ;
        RECT  18.672 0 18.696 0.084 ;
    END
  END i[59]
  PIN i[5]
    DIRECTION INPUT ;
    USE SIGNAL ;
    PORT
      LAYER M5 ;
        RECT  13.488 0 13.512 0.084 ;
    END
  END i[5]
  PIN i[60]
    DIRECTION INPUT ;
    USE SIGNAL ;
    PORT
      LAYER M5 ;
        RECT  18.768 0 18.792 0.084 ;
    END
  END i[60]
  PIN i[61]
    DIRECTION INPUT ;
    USE SIGNAL ;
    PORT
      LAYER M5 ;
        RECT  18.864 0 18.888 0.084 ;
    END
  END i[61]
  PIN i[62]
    DIRECTION INPUT ;
    USE SIGNAL ;
    PORT
      LAYER M5 ;
        RECT  18.96 0 18.984 0.084 ;
    END
  END i[62]
  PIN i[63]
    DIRECTION INPUT ;
    USE SIGNAL ;
    PORT
      LAYER M5 ;
        RECT  19.056 0 19.08 0.084 ;
    END
  END i[63]
  PIN i[64]
    DIRECTION INPUT ;
    USE SIGNAL ;
    PORT
      LAYER M5 ;
        RECT  3.792 0 3.816 0.084 ;
    END
  END i[64]
  PIN i[65]
    DIRECTION INPUT ;
    USE SIGNAL ;
    PORT
      LAYER M5 ;
        RECT  3.888 0 3.912 0.084 ;
    END
  END i[65]
  PIN i[66]
    DIRECTION INPUT ;
    USE SIGNAL ;
    PORT
      LAYER M5 ;
        RECT  3.984 0 4.008 0.084 ;
    END
  END i[66]
  PIN i[67]
    DIRECTION INPUT ;
    USE SIGNAL ;
    PORT
      LAYER M5 ;
        RECT  4.08 0 4.104 0.084 ;
    END
  END i[67]
  PIN i[68]
    DIRECTION INPUT ;
    USE SIGNAL ;
    PORT
      LAYER M5 ;
        RECT  4.176 0 4.2 0.084 ;
    END
  END i[68]
  PIN i[69]
    DIRECTION INPUT ;
    USE SIGNAL ;
    PORT
      LAYER M5 ;
        RECT  4.272 0 4.296 0.084 ;
    END
  END i[69]
  PIN i[6]
    DIRECTION INPUT ;
    USE SIGNAL ;
    PORT
      LAYER M5 ;
        RECT  13.584 0 13.608 0.084 ;
    END
  END i[6]
  PIN i[70]
    DIRECTION INPUT ;
    USE SIGNAL ;
    PORT
      LAYER M5 ;
        RECT  4.368 0 4.392 0.084 ;
    END
  END i[70]
  PIN i[71]
    DIRECTION INPUT ;
    USE SIGNAL ;
    PORT
      LAYER M5 ;
        RECT  4.464 0 4.488 0.084 ;
    END
  END i[71]
  PIN i[72]
    DIRECTION INPUT ;
    USE SIGNAL ;
    PORT
      LAYER M5 ;
        RECT  4.56 0 4.584 0.084 ;
    END
  END i[72]
  PIN i[73]
    DIRECTION INPUT ;
    USE SIGNAL ;
    PORT
      LAYER M5 ;
        RECT  4.656 0 4.68 0.084 ;
    END
  END i[73]
  PIN i[74]
    DIRECTION INPUT ;
    USE SIGNAL ;
    PORT
      LAYER M5 ;
        RECT  4.752 0 4.776 0.084 ;
    END
  END i[74]
  PIN i[75]
    DIRECTION INPUT ;
    USE SIGNAL ;
    PORT
      LAYER M5 ;
        RECT  4.848 0 4.872 0.084 ;
    END
  END i[75]
  PIN i[76]
    DIRECTION INPUT ;
    USE SIGNAL ;
    PORT
      LAYER M5 ;
        RECT  4.944 0 4.968 0.084 ;
    END
  END i[76]
  PIN i[77]
    DIRECTION INPUT ;
    USE SIGNAL ;
    PORT
      LAYER M5 ;
        RECT  5.04 0 5.064 0.084 ;
    END
  END i[77]
  PIN i[78]
    DIRECTION INPUT ;
    USE SIGNAL ;
    PORT
      LAYER M5 ;
        RECT  5.136 0 5.16 0.084 ;
    END
  END i[78]
  PIN i[79]
    DIRECTION INPUT ;
    USE SIGNAL ;
    PORT
      LAYER M5 ;
        RECT  5.232 0 5.256 0.084 ;
    END
  END i[79]
  PIN i[7]
    DIRECTION INPUT ;
    USE SIGNAL ;
    PORT
      LAYER M5 ;
        RECT  13.68 0 13.704 0.084 ;
    END
  END i[7]
  PIN i[80]
    DIRECTION INPUT ;
    USE SIGNAL ;
    PORT
      LAYER M5 ;
        RECT  5.328 0 5.352 0.084 ;
    END
  END i[80]
  PIN i[81]
    DIRECTION INPUT ;
    USE SIGNAL ;
    PORT
      LAYER M5 ;
        RECT  5.424 0 5.448 0.084 ;
    END
  END i[81]
  PIN i[82]
    DIRECTION INPUT ;
    USE SIGNAL ;
    PORT
      LAYER M5 ;
        RECT  5.52 0 5.544 0.084 ;
    END
  END i[82]
  PIN i[83]
    DIRECTION INPUT ;
    USE SIGNAL ;
    PORT
      LAYER M5 ;
        RECT  5.616 0 5.64 0.084 ;
    END
  END i[83]
  PIN i[84]
    DIRECTION INPUT ;
    USE SIGNAL ;
    PORT
      LAYER M5 ;
        RECT  5.712 0 5.736 0.084 ;
    END
  END i[84]
  PIN i[85]
    DIRECTION INPUT ;
    USE SIGNAL ;
    PORT
      LAYER M5 ;
        RECT  5.808 0 5.832 0.084 ;
    END
  END i[85]
  PIN i[86]
    DIRECTION INPUT ;
    USE SIGNAL ;
    PORT
      LAYER M5 ;
        RECT  5.904 0 5.928 0.084 ;
    END
  END i[86]
  PIN i[87]
    DIRECTION INPUT ;
    USE SIGNAL ;
    PORT
      LAYER M5 ;
        RECT  6 0 6.024 0.084 ;
    END
  END i[87]
  PIN i[88]
    DIRECTION INPUT ;
    USE SIGNAL ;
    PORT
      LAYER M5 ;
        RECT  6.096 0 6.12 0.084 ;
    END
  END i[88]
  PIN i[89]
    DIRECTION INPUT ;
    USE SIGNAL ;
    PORT
      LAYER M5 ;
        RECT  6.192 0 6.216 0.084 ;
    END
  END i[89]
  PIN i[8]
    DIRECTION INPUT ;
    USE SIGNAL ;
    PORT
      LAYER M5 ;
        RECT  13.776 0 13.8 0.084 ;
    END
  END i[8]
  PIN i[90]
    DIRECTION INPUT ;
    USE SIGNAL ;
    PORT
      LAYER M5 ;
        RECT  6.288 0 6.312 0.084 ;
    END
  END i[90]
  PIN i[91]
    DIRECTION INPUT ;
    USE SIGNAL ;
    PORT
      LAYER M5 ;
        RECT  6.384 0 6.408 0.084 ;
    END
  END i[91]
  PIN i[92]
    DIRECTION INPUT ;
    USE SIGNAL ;
    PORT
      LAYER M5 ;
        RECT  6.48 0 6.504 0.084 ;
    END
  END i[92]
  PIN i[93]
    DIRECTION INPUT ;
    USE SIGNAL ;
    PORT
      LAYER M5 ;
        RECT  6.576 0 6.6 0.084 ;
    END
  END i[93]
  PIN i[94]
    DIRECTION INPUT ;
    USE SIGNAL ;
    PORT
      LAYER M5 ;
        RECT  6.672 0 6.696 0.084 ;
    END
  END i[94]
  PIN i[95]
    DIRECTION INPUT ;
    USE SIGNAL ;
    PORT
      LAYER M5 ;
        RECT  6.768 0 6.792 0.084 ;
    END
  END i[95]
  PIN i[96]
    DIRECTION INPUT ;
    USE SIGNAL ;
    PORT
      LAYER M5 ;
        RECT  6.864 0 6.888 0.084 ;
    END
  END i[96]
  PIN i[97]
    DIRECTION INPUT ;
    USE SIGNAL ;
    PORT
      LAYER M5 ;
        RECT  6.96 0 6.984 0.084 ;
    END
  END i[97]
  PIN i[98]
    DIRECTION INPUT ;
    USE SIGNAL ;
    PORT
      LAYER M5 ;
        RECT  7.056 0 7.08 0.084 ;
    END
  END i[98]
  PIN i[99]
    DIRECTION INPUT ;
    USE SIGNAL ;
    PORT
      LAYER M5 ;
        RECT  7.152 0 7.176 0.084 ;
    END
  END i[99]
  PIN i[9]
    DIRECTION INPUT ;
    USE SIGNAL ;
    PORT
      LAYER M5 ;
        RECT  13.872 0 13.896 0.084 ;
    END
  END i[9]
  PIN o[0]
    DIRECTION OUTPUT ;
    USE SIGNAL ;
    PORT
      LAYER M5 ;
        RECT  27.696 19.356 27.72 19.44 ;
    END
  END o[0]
  PIN o[100]
    DIRECTION OUTPUT ;
    USE SIGNAL ;
    PORT
      LAYER M5 ;
        RECT  15.792 19.356 15.816 19.44 ;
    END
  END o[100]
  PIN o[101]
    DIRECTION OUTPUT ;
    USE SIGNAL ;
    PORT
      LAYER M5 ;
        RECT  15.888 19.356 15.912 19.44 ;
    END
  END o[101]
  PIN o[102]
    DIRECTION OUTPUT ;
    USE SIGNAL ;
    PORT
      LAYER M5 ;
        RECT  15.984 19.356 16.008 19.44 ;
    END
  END o[102]
  PIN o[103]
    DIRECTION OUTPUT ;
    USE SIGNAL ;
    PORT
      LAYER M5 ;
        RECT  16.08 19.356 16.104 19.44 ;
    END
  END o[103]
  PIN o[104]
    DIRECTION OUTPUT ;
    USE SIGNAL ;
    PORT
      LAYER M5 ;
        RECT  16.176 19.356 16.2 19.44 ;
    END
  END o[104]
  PIN o[105]
    DIRECTION OUTPUT ;
    USE SIGNAL ;
    PORT
      LAYER M5 ;
        RECT  16.272 19.356 16.296 19.44 ;
    END
  END o[105]
  PIN o[106]
    DIRECTION OUTPUT ;
    USE SIGNAL ;
    PORT
      LAYER M5 ;
        RECT  16.368 19.356 16.392 19.44 ;
    END
  END o[106]
  PIN o[107]
    DIRECTION OUTPUT ;
    USE SIGNAL ;
    PORT
      LAYER M5 ;
        RECT  16.464 19.356 16.488 19.44 ;
    END
  END o[107]
  PIN o[108]
    DIRECTION OUTPUT ;
    USE SIGNAL ;
    PORT
      LAYER M5 ;
        RECT  16.56 19.356 16.584 19.44 ;
    END
  END o[108]
  PIN o[109]
    DIRECTION OUTPUT ;
    USE SIGNAL ;
    PORT
      LAYER M5 ;
        RECT  16.656 19.356 16.68 19.44 ;
    END
  END o[109]
  PIN o[10]
    DIRECTION OUTPUT ;
    USE SIGNAL ;
    PORT
      LAYER M5 ;
        RECT  28.656 19.356 28.68 19.44 ;
    END
  END o[10]
  PIN o[110]
    DIRECTION OUTPUT ;
    USE SIGNAL ;
    PORT
      LAYER M5 ;
        RECT  16.752 19.356 16.776 19.44 ;
    END
  END o[110]
  PIN o[111]
    DIRECTION OUTPUT ;
    USE SIGNAL ;
    PORT
      LAYER M5 ;
        RECT  16.848 19.356 16.872 19.44 ;
    END
  END o[111]
  PIN o[112]
    DIRECTION OUTPUT ;
    USE SIGNAL ;
    PORT
      LAYER M5 ;
        RECT  16.944 19.356 16.968 19.44 ;
    END
  END o[112]
  PIN o[113]
    DIRECTION OUTPUT ;
    USE SIGNAL ;
    PORT
      LAYER M5 ;
        RECT  17.04 19.356 17.064 19.44 ;
    END
  END o[113]
  PIN o[114]
    DIRECTION OUTPUT ;
    USE SIGNAL ;
    PORT
      LAYER M5 ;
        RECT  17.136 19.356 17.16 19.44 ;
    END
  END o[114]
  PIN o[115]
    DIRECTION OUTPUT ;
    USE SIGNAL ;
    PORT
      LAYER M5 ;
        RECT  17.232 19.356 17.256 19.44 ;
    END
  END o[115]
  PIN o[116]
    DIRECTION OUTPUT ;
    USE SIGNAL ;
    PORT
      LAYER M5 ;
        RECT  17.328 19.356 17.352 19.44 ;
    END
  END o[116]
  PIN o[117]
    DIRECTION OUTPUT ;
    USE SIGNAL ;
    PORT
      LAYER M5 ;
        RECT  17.424 19.356 17.448 19.44 ;
    END
  END o[117]
  PIN o[118]
    DIRECTION OUTPUT ;
    USE SIGNAL ;
    PORT
      LAYER M5 ;
        RECT  17.52 19.356 17.544 19.44 ;
    END
  END o[118]
  PIN o[119]
    DIRECTION OUTPUT ;
    USE SIGNAL ;
    PORT
      LAYER M5 ;
        RECT  17.616 19.356 17.64 19.44 ;
    END
  END o[119]
  PIN o[11]
    DIRECTION OUTPUT ;
    USE SIGNAL ;
    PORT
      LAYER M5 ;
        RECT  28.752 19.356 28.776 19.44 ;
    END
  END o[11]
  PIN o[120]
    DIRECTION OUTPUT ;
    USE SIGNAL ;
    PORT
      LAYER M5 ;
        RECT  17.712 19.356 17.736 19.44 ;
    END
  END o[120]
  PIN o[121]
    DIRECTION OUTPUT ;
    USE SIGNAL ;
    PORT
      LAYER M5 ;
        RECT  17.808 19.356 17.832 19.44 ;
    END
  END o[121]
  PIN o[122]
    DIRECTION OUTPUT ;
    USE SIGNAL ;
    PORT
      LAYER M5 ;
        RECT  17.904 19.356 17.928 19.44 ;
    END
  END o[122]
  PIN o[123]
    DIRECTION OUTPUT ;
    USE SIGNAL ;
    PORT
      LAYER M5 ;
        RECT  18 19.356 18.024 19.44 ;
    END
  END o[123]
  PIN o[124]
    DIRECTION OUTPUT ;
    USE SIGNAL ;
    PORT
      LAYER M5 ;
        RECT  18.096 19.356 18.12 19.44 ;
    END
  END o[124]
  PIN o[125]
    DIRECTION OUTPUT ;
    USE SIGNAL ;
    PORT
      LAYER M5 ;
        RECT  18.192 19.356 18.216 19.44 ;
    END
  END o[125]
  PIN o[126]
    DIRECTION OUTPUT ;
    USE SIGNAL ;
    PORT
      LAYER M5 ;
        RECT  18.288 19.356 18.312 19.44 ;
    END
  END o[126]
  PIN o[127]
    DIRECTION OUTPUT ;
    USE SIGNAL ;
    PORT
      LAYER M5 ;
        RECT  18.384 19.356 18.408 19.44 ;
    END
  END o[127]
  PIN o[128]
    DIRECTION OUTPUT ;
    USE SIGNAL ;
    PORT
      LAYER M5 ;
        RECT  18.48 19.356 18.504 19.44 ;
    END
  END o[128]
  PIN o[129]
    DIRECTION OUTPUT ;
    USE SIGNAL ;
    PORT
      LAYER M5 ;
        RECT  18.576 19.356 18.6 19.44 ;
    END
  END o[129]
  PIN o[12]
    DIRECTION OUTPUT ;
    USE SIGNAL ;
    PORT
      LAYER M5 ;
        RECT  28.848 19.356 28.872 19.44 ;
    END
  END o[12]
  PIN o[130]
    DIRECTION OUTPUT ;
    USE SIGNAL ;
    PORT
      LAYER M5 ;
        RECT  18.672 19.356 18.696 19.44 ;
    END
  END o[130]
  PIN o[131]
    DIRECTION OUTPUT ;
    USE SIGNAL ;
    PORT
      LAYER M5 ;
        RECT  18.768 19.356 18.792 19.44 ;
    END
  END o[131]
  PIN o[132]
    DIRECTION OUTPUT ;
    USE SIGNAL ;
    PORT
      LAYER M5 ;
        RECT  18.864 19.356 18.888 19.44 ;
    END
  END o[132]
  PIN o[133]
    DIRECTION OUTPUT ;
    USE SIGNAL ;
    PORT
      LAYER M5 ;
        RECT  18.96 19.356 18.984 19.44 ;
    END
  END o[133]
  PIN o[134]
    DIRECTION OUTPUT ;
    USE SIGNAL ;
    PORT
      LAYER M5 ;
        RECT  19.056 19.356 19.08 19.44 ;
    END
  END o[134]
  PIN o[135]
    DIRECTION OUTPUT ;
    USE SIGNAL ;
    PORT
      LAYER M5 ;
        RECT  19.152 19.356 19.176 19.44 ;
    END
  END o[135]
  PIN o[136]
    DIRECTION OUTPUT ;
    USE SIGNAL ;
    PORT
      LAYER M5 ;
        RECT  19.248 19.356 19.272 19.44 ;
    END
  END o[136]
  PIN o[137]
    DIRECTION OUTPUT ;
    USE SIGNAL ;
    PORT
      LAYER M5 ;
        RECT  19.344 19.356 19.368 19.44 ;
    END
  END o[137]
  PIN o[138]
    DIRECTION OUTPUT ;
    USE SIGNAL ;
    PORT
      LAYER M5 ;
        RECT  19.44 19.356 19.464 19.44 ;
    END
  END o[138]
  PIN o[139]
    DIRECTION OUTPUT ;
    USE SIGNAL ;
    PORT
      LAYER M5 ;
        RECT  19.536 19.356 19.56 19.44 ;
    END
  END o[139]
  PIN o[13]
    DIRECTION OUTPUT ;
    USE SIGNAL ;
    PORT
      LAYER M5 ;
        RECT  28.944 19.356 28.968 19.44 ;
    END
  END o[13]
  PIN o[140]
    DIRECTION OUTPUT ;
    USE SIGNAL ;
    PORT
      LAYER M5 ;
        RECT  19.632 19.356 19.656 19.44 ;
    END
  END o[140]
  PIN o[141]
    DIRECTION OUTPUT ;
    USE SIGNAL ;
    PORT
      LAYER M5 ;
        RECT  19.728 19.356 19.752 19.44 ;
    END
  END o[141]
  PIN o[142]
    DIRECTION OUTPUT ;
    USE SIGNAL ;
    PORT
      LAYER M5 ;
        RECT  19.824 19.356 19.848 19.44 ;
    END
  END o[142]
  PIN o[143]
    DIRECTION OUTPUT ;
    USE SIGNAL ;
    PORT
      LAYER M5 ;
        RECT  19.92 19.356 19.944 19.44 ;
    END
  END o[143]
  PIN o[144]
    DIRECTION OUTPUT ;
    USE SIGNAL ;
    PORT
      LAYER M5 ;
        RECT  20.016 19.356 20.04 19.44 ;
    END
  END o[144]
  PIN o[145]
    DIRECTION OUTPUT ;
    USE SIGNAL ;
    PORT
      LAYER M5 ;
        RECT  20.112 19.356 20.136 19.44 ;
    END
  END o[145]
  PIN o[146]
    DIRECTION OUTPUT ;
    USE SIGNAL ;
    PORT
      LAYER M5 ;
        RECT  20.208 19.356 20.232 19.44 ;
    END
  END o[146]
  PIN o[147]
    DIRECTION OUTPUT ;
    USE SIGNAL ;
    PORT
      LAYER M5 ;
        RECT  20.304 19.356 20.328 19.44 ;
    END
  END o[147]
  PIN o[148]
    DIRECTION OUTPUT ;
    USE SIGNAL ;
    PORT
      LAYER M5 ;
        RECT  20.4 19.356 20.424 19.44 ;
    END
  END o[148]
  PIN o[149]
    DIRECTION OUTPUT ;
    USE SIGNAL ;
    PORT
      LAYER M5 ;
        RECT  20.496 19.356 20.52 19.44 ;
    END
  END o[149]
  PIN o[14]
    DIRECTION OUTPUT ;
    USE SIGNAL ;
    PORT
      LAYER M5 ;
        RECT  29.04 19.356 29.064 19.44 ;
    END
  END o[14]
  PIN o[150]
    DIRECTION OUTPUT ;
    USE SIGNAL ;
    PORT
      LAYER M5 ;
        RECT  20.592 19.356 20.616 19.44 ;
    END
  END o[150]
  PIN o[151]
    DIRECTION OUTPUT ;
    USE SIGNAL ;
    PORT
      LAYER M5 ;
        RECT  20.688 19.356 20.712 19.44 ;
    END
  END o[151]
  PIN o[152]
    DIRECTION OUTPUT ;
    USE SIGNAL ;
    PORT
      LAYER M5 ;
        RECT  20.784 19.356 20.808 19.44 ;
    END
  END o[152]
  PIN o[153]
    DIRECTION OUTPUT ;
    USE SIGNAL ;
    PORT
      LAYER M5 ;
        RECT  20.88 19.356 20.904 19.44 ;
    END
  END o[153]
  PIN o[154]
    DIRECTION OUTPUT ;
    USE SIGNAL ;
    PORT
      LAYER M5 ;
        RECT  20.976 19.356 21 19.44 ;
    END
  END o[154]
  PIN o[155]
    DIRECTION OUTPUT ;
    USE SIGNAL ;
    PORT
      LAYER M5 ;
        RECT  21.072 19.356 21.096 19.44 ;
    END
  END o[155]
  PIN o[156]
    DIRECTION OUTPUT ;
    USE SIGNAL ;
    PORT
      LAYER M5 ;
        RECT  21.168 19.356 21.192 19.44 ;
    END
  END o[156]
  PIN o[157]
    DIRECTION OUTPUT ;
    USE SIGNAL ;
    PORT
      LAYER M5 ;
        RECT  21.264 19.356 21.288 19.44 ;
    END
  END o[157]
  PIN o[158]
    DIRECTION OUTPUT ;
    USE SIGNAL ;
    PORT
      LAYER M5 ;
        RECT  21.36 19.356 21.384 19.44 ;
    END
  END o[158]
  PIN o[159]
    DIRECTION OUTPUT ;
    USE SIGNAL ;
    PORT
      LAYER M5 ;
        RECT  21.456 19.356 21.48 19.44 ;
    END
  END o[159]
  PIN o[15]
    DIRECTION OUTPUT ;
    USE SIGNAL ;
    PORT
      LAYER M5 ;
        RECT  29.136 19.356 29.16 19.44 ;
    END
  END o[15]
  PIN o[160]
    DIRECTION OUTPUT ;
    USE SIGNAL ;
    PORT
      LAYER M5 ;
        RECT  30.768 19.356 30.792 19.44 ;
    END
  END o[160]
  PIN o[161]
    DIRECTION OUTPUT ;
    USE SIGNAL ;
    PORT
      LAYER M5 ;
        RECT  30.864 19.356 30.888 19.44 ;
    END
  END o[161]
  PIN o[162]
    DIRECTION OUTPUT ;
    USE SIGNAL ;
    PORT
      LAYER M5 ;
        RECT  30.96 19.356 30.984 19.44 ;
    END
  END o[162]
  PIN o[163]
    DIRECTION OUTPUT ;
    USE SIGNAL ;
    PORT
      LAYER M5 ;
        RECT  31.056 19.356 31.08 19.44 ;
    END
  END o[163]
  PIN o[164]
    DIRECTION OUTPUT ;
    USE SIGNAL ;
    PORT
      LAYER M5 ;
        RECT  31.152 19.356 31.176 19.44 ;
    END
  END o[164]
  PIN o[165]
    DIRECTION OUTPUT ;
    USE SIGNAL ;
    PORT
      LAYER M5 ;
        RECT  31.248 19.356 31.272 19.44 ;
    END
  END o[165]
  PIN o[166]
    DIRECTION OUTPUT ;
    USE SIGNAL ;
    PORT
      LAYER M5 ;
        RECT  31.344 19.356 31.368 19.44 ;
    END
  END o[166]
  PIN o[167]
    DIRECTION OUTPUT ;
    USE SIGNAL ;
    PORT
      LAYER M5 ;
        RECT  31.44 19.356 31.464 19.44 ;
    END
  END o[167]
  PIN o[168]
    DIRECTION OUTPUT ;
    USE SIGNAL ;
    PORT
      LAYER M5 ;
        RECT  31.536 19.356 31.56 19.44 ;
    END
  END o[168]
  PIN o[169]
    DIRECTION OUTPUT ;
    USE SIGNAL ;
    PORT
      LAYER M5 ;
        RECT  31.632 19.356 31.656 19.44 ;
    END
  END o[169]
  PIN o[16]
    DIRECTION OUTPUT ;
    USE SIGNAL ;
    PORT
      LAYER M5 ;
        RECT  29.232 19.356 29.256 19.44 ;
    END
  END o[16]
  PIN o[170]
    DIRECTION OUTPUT ;
    USE SIGNAL ;
    PORT
      LAYER M5 ;
        RECT  31.728 19.356 31.752 19.44 ;
    END
  END o[170]
  PIN o[171]
    DIRECTION OUTPUT ;
    USE SIGNAL ;
    PORT
      LAYER M5 ;
        RECT  31.824 19.356 31.848 19.44 ;
    END
  END o[171]
  PIN o[172]
    DIRECTION OUTPUT ;
    USE SIGNAL ;
    PORT
      LAYER M5 ;
        RECT  31.92 19.356 31.944 19.44 ;
    END
  END o[172]
  PIN o[173]
    DIRECTION OUTPUT ;
    USE SIGNAL ;
    PORT
      LAYER M5 ;
        RECT  32.016 19.356 32.04 19.44 ;
    END
  END o[173]
  PIN o[174]
    DIRECTION OUTPUT ;
    USE SIGNAL ;
    PORT
      LAYER M5 ;
        RECT  32.112 19.356 32.136 19.44 ;
    END
  END o[174]
  PIN o[175]
    DIRECTION OUTPUT ;
    USE SIGNAL ;
    PORT
      LAYER M5 ;
        RECT  32.208 19.356 32.232 19.44 ;
    END
  END o[175]
  PIN o[176]
    DIRECTION OUTPUT ;
    USE SIGNAL ;
    PORT
      LAYER M5 ;
        RECT  32.304 19.356 32.328 19.44 ;
    END
  END o[176]
  PIN o[177]
    DIRECTION OUTPUT ;
    USE SIGNAL ;
    PORT
      LAYER M5 ;
        RECT  32.4 19.356 32.424 19.44 ;
    END
  END o[177]
  PIN o[178]
    DIRECTION OUTPUT ;
    USE SIGNAL ;
    PORT
      LAYER M5 ;
        RECT  32.496 19.356 32.52 19.44 ;
    END
  END o[178]
  PIN o[179]
    DIRECTION OUTPUT ;
    USE SIGNAL ;
    PORT
      LAYER M5 ;
        RECT  32.592 19.356 32.616 19.44 ;
    END
  END o[179]
  PIN o[17]
    DIRECTION OUTPUT ;
    USE SIGNAL ;
    PORT
      LAYER M5 ;
        RECT  29.328 19.356 29.352 19.44 ;
    END
  END o[17]
  PIN o[180]
    DIRECTION OUTPUT ;
    USE SIGNAL ;
    PORT
      LAYER M5 ;
        RECT  32.688 19.356 32.712 19.44 ;
    END
  END o[180]
  PIN o[181]
    DIRECTION OUTPUT ;
    USE SIGNAL ;
    PORT
      LAYER M5 ;
        RECT  32.784 19.356 32.808 19.44 ;
    END
  END o[181]
  PIN o[182]
    DIRECTION OUTPUT ;
    USE SIGNAL ;
    PORT
      LAYER M5 ;
        RECT  32.88 19.356 32.904 19.44 ;
    END
  END o[182]
  PIN o[183]
    DIRECTION OUTPUT ;
    USE SIGNAL ;
    PORT
      LAYER M5 ;
        RECT  32.976 19.356 33 19.44 ;
    END
  END o[183]
  PIN o[184]
    DIRECTION OUTPUT ;
    USE SIGNAL ;
    PORT
      LAYER M5 ;
        RECT  33.072 19.356 33.096 19.44 ;
    END
  END o[184]
  PIN o[185]
    DIRECTION OUTPUT ;
    USE SIGNAL ;
    PORT
      LAYER M5 ;
        RECT  33.168 19.356 33.192 19.44 ;
    END
  END o[185]
  PIN o[186]
    DIRECTION OUTPUT ;
    USE SIGNAL ;
    PORT
      LAYER M5 ;
        RECT  33.264 19.356 33.288 19.44 ;
    END
  END o[186]
  PIN o[187]
    DIRECTION OUTPUT ;
    USE SIGNAL ;
    PORT
      LAYER M5 ;
        RECT  33.36 19.356 33.384 19.44 ;
    END
  END o[187]
  PIN o[188]
    DIRECTION OUTPUT ;
    USE SIGNAL ;
    PORT
      LAYER M5 ;
        RECT  33.456 19.356 33.48 19.44 ;
    END
  END o[188]
  PIN o[189]
    DIRECTION OUTPUT ;
    USE SIGNAL ;
    PORT
      LAYER M5 ;
        RECT  33.552 19.356 33.576 19.44 ;
    END
  END o[189]
  PIN o[18]
    DIRECTION OUTPUT ;
    USE SIGNAL ;
    PORT
      LAYER M5 ;
        RECT  29.424 19.356 29.448 19.44 ;
    END
  END o[18]
  PIN o[190]
    DIRECTION OUTPUT ;
    USE SIGNAL ;
    PORT
      LAYER M5 ;
        RECT  33.648 19.356 33.672 19.44 ;
    END
  END o[190]
  PIN o[191]
    DIRECTION OUTPUT ;
    USE SIGNAL ;
    PORT
      LAYER M5 ;
        RECT  33.744 19.356 33.768 19.44 ;
    END
  END o[191]
  PIN o[192]
    DIRECTION OUTPUT ;
    USE SIGNAL ;
    PORT
      LAYER M5 ;
        RECT  11.568 19.356 11.592 19.44 ;
    END
  END o[192]
  PIN o[193]
    DIRECTION OUTPUT ;
    USE SIGNAL ;
    PORT
      LAYER M5 ;
        RECT  11.664 19.356 11.688 19.44 ;
    END
  END o[193]
  PIN o[194]
    DIRECTION OUTPUT ;
    USE SIGNAL ;
    PORT
      LAYER M5 ;
        RECT  11.76 19.356 11.784 19.44 ;
    END
  END o[194]
  PIN o[195]
    DIRECTION OUTPUT ;
    USE SIGNAL ;
    PORT
      LAYER M5 ;
        RECT  11.856 19.356 11.88 19.44 ;
    END
  END o[195]
  PIN o[196]
    DIRECTION OUTPUT ;
    USE SIGNAL ;
    PORT
      LAYER M5 ;
        RECT  11.952 19.356 11.976 19.44 ;
    END
  END o[196]
  PIN o[197]
    DIRECTION OUTPUT ;
    USE SIGNAL ;
    PORT
      LAYER M5 ;
        RECT  12.048 19.356 12.072 19.44 ;
    END
  END o[197]
  PIN o[198]
    DIRECTION OUTPUT ;
    USE SIGNAL ;
    PORT
      LAYER M5 ;
        RECT  12.144 19.356 12.168 19.44 ;
    END
  END o[198]
  PIN o[199]
    DIRECTION OUTPUT ;
    USE SIGNAL ;
    PORT
      LAYER M5 ;
        RECT  12.24 19.356 12.264 19.44 ;
    END
  END o[199]
  PIN o[19]
    DIRECTION OUTPUT ;
    USE SIGNAL ;
    PORT
      LAYER M5 ;
        RECT  29.52 19.356 29.544 19.44 ;
    END
  END o[19]
  PIN o[1]
    DIRECTION OUTPUT ;
    USE SIGNAL ;
    PORT
      LAYER M5 ;
        RECT  27.792 19.356 27.816 19.44 ;
    END
  END o[1]
  PIN o[200]
    DIRECTION OUTPUT ;
    USE SIGNAL ;
    PORT
      LAYER M5 ;
        RECT  12.336 19.356 12.36 19.44 ;
    END
  END o[200]
  PIN o[201]
    DIRECTION OUTPUT ;
    USE SIGNAL ;
    PORT
      LAYER M5 ;
        RECT  12.432 19.356 12.456 19.44 ;
    END
  END o[201]
  PIN o[202]
    DIRECTION OUTPUT ;
    USE SIGNAL ;
    PORT
      LAYER M5 ;
        RECT  12.528 19.356 12.552 19.44 ;
    END
  END o[202]
  PIN o[203]
    DIRECTION OUTPUT ;
    USE SIGNAL ;
    PORT
      LAYER M5 ;
        RECT  12.624 19.356 12.648 19.44 ;
    END
  END o[203]
  PIN o[204]
    DIRECTION OUTPUT ;
    USE SIGNAL ;
    PORT
      LAYER M5 ;
        RECT  12.72 19.356 12.744 19.44 ;
    END
  END o[204]
  PIN o[205]
    DIRECTION OUTPUT ;
    USE SIGNAL ;
    PORT
      LAYER M5 ;
        RECT  12.816 19.356 12.84 19.44 ;
    END
  END o[205]
  PIN o[206]
    DIRECTION OUTPUT ;
    USE SIGNAL ;
    PORT
      LAYER M5 ;
        RECT  12.912 19.356 12.936 19.44 ;
    END
  END o[206]
  PIN o[207]
    DIRECTION OUTPUT ;
    USE SIGNAL ;
    PORT
      LAYER M5 ;
        RECT  13.008 19.356 13.032 19.44 ;
    END
  END o[207]
  PIN o[208]
    DIRECTION OUTPUT ;
    USE SIGNAL ;
    PORT
      LAYER M5 ;
        RECT  13.104 19.356 13.128 19.44 ;
    END
  END o[208]
  PIN o[209]
    DIRECTION OUTPUT ;
    USE SIGNAL ;
    PORT
      LAYER M5 ;
        RECT  13.2 19.356 13.224 19.44 ;
    END
  END o[209]
  PIN o[20]
    DIRECTION OUTPUT ;
    USE SIGNAL ;
    PORT
      LAYER M5 ;
        RECT  29.616 19.356 29.64 19.44 ;
    END
  END o[20]
  PIN o[210]
    DIRECTION OUTPUT ;
    USE SIGNAL ;
    PORT
      LAYER M5 ;
        RECT  13.296 19.356 13.32 19.44 ;
    END
  END o[210]
  PIN o[211]
    DIRECTION OUTPUT ;
    USE SIGNAL ;
    PORT
      LAYER M5 ;
        RECT  13.392 19.356 13.416 19.44 ;
    END
  END o[211]
  PIN o[212]
    DIRECTION OUTPUT ;
    USE SIGNAL ;
    PORT
      LAYER M5 ;
        RECT  13.488 19.356 13.512 19.44 ;
    END
  END o[212]
  PIN o[213]
    DIRECTION OUTPUT ;
    USE SIGNAL ;
    PORT
      LAYER M5 ;
        RECT  13.584 19.356 13.608 19.44 ;
    END
  END o[213]
  PIN o[214]
    DIRECTION OUTPUT ;
    USE SIGNAL ;
    PORT
      LAYER M5 ;
        RECT  13.68 19.356 13.704 19.44 ;
    END
  END o[214]
  PIN o[215]
    DIRECTION OUTPUT ;
    USE SIGNAL ;
    PORT
      LAYER M5 ;
        RECT  13.776 19.356 13.8 19.44 ;
    END
  END o[215]
  PIN o[216]
    DIRECTION OUTPUT ;
    USE SIGNAL ;
    PORT
      LAYER M5 ;
        RECT  13.872 19.356 13.896 19.44 ;
    END
  END o[216]
  PIN o[217]
    DIRECTION OUTPUT ;
    USE SIGNAL ;
    PORT
      LAYER M5 ;
        RECT  13.968 19.356 13.992 19.44 ;
    END
  END o[217]
  PIN o[218]
    DIRECTION OUTPUT ;
    USE SIGNAL ;
    PORT
      LAYER M5 ;
        RECT  14.064 19.356 14.088 19.44 ;
    END
  END o[218]
  PIN o[219]
    DIRECTION OUTPUT ;
    USE SIGNAL ;
    PORT
      LAYER M5 ;
        RECT  14.16 19.356 14.184 19.44 ;
    END
  END o[219]
  PIN o[21]
    DIRECTION OUTPUT ;
    USE SIGNAL ;
    PORT
      LAYER M5 ;
        RECT  29.712 19.356 29.736 19.44 ;
    END
  END o[21]
  PIN o[220]
    DIRECTION OUTPUT ;
    USE SIGNAL ;
    PORT
      LAYER M5 ;
        RECT  14.256 19.356 14.28 19.44 ;
    END
  END o[220]
  PIN o[221]
    DIRECTION OUTPUT ;
    USE SIGNAL ;
    PORT
      LAYER M5 ;
        RECT  14.352 19.356 14.376 19.44 ;
    END
  END o[221]
  PIN o[222]
    DIRECTION OUTPUT ;
    USE SIGNAL ;
    PORT
      LAYER M5 ;
        RECT  14.448 19.356 14.472 19.44 ;
    END
  END o[222]
  PIN o[223]
    DIRECTION OUTPUT ;
    USE SIGNAL ;
    PORT
      LAYER M5 ;
        RECT  14.544 19.356 14.568 19.44 ;
    END
  END o[223]
  PIN o[224]
    DIRECTION OUTPUT ;
    USE SIGNAL ;
    PORT
      LAYER M5 ;
        RECT  8.496 19.356 8.52 19.44 ;
    END
  END o[224]
  PIN o[225]
    DIRECTION OUTPUT ;
    USE SIGNAL ;
    PORT
      LAYER M5 ;
        RECT  8.592 19.356 8.616 19.44 ;
    END
  END o[225]
  PIN o[226]
    DIRECTION OUTPUT ;
    USE SIGNAL ;
    PORT
      LAYER M5 ;
        RECT  8.688 19.356 8.712 19.44 ;
    END
  END o[226]
  PIN o[227]
    DIRECTION OUTPUT ;
    USE SIGNAL ;
    PORT
      LAYER M5 ;
        RECT  8.784 19.356 8.808 19.44 ;
    END
  END o[227]
  PIN o[228]
    DIRECTION OUTPUT ;
    USE SIGNAL ;
    PORT
      LAYER M5 ;
        RECT  8.88 19.356 8.904 19.44 ;
    END
  END o[228]
  PIN o[229]
    DIRECTION OUTPUT ;
    USE SIGNAL ;
    PORT
      LAYER M5 ;
        RECT  8.976 19.356 9 19.44 ;
    END
  END o[229]
  PIN o[22]
    DIRECTION OUTPUT ;
    USE SIGNAL ;
    PORT
      LAYER M5 ;
        RECT  29.808 19.356 29.832 19.44 ;
    END
  END o[22]
  PIN o[230]
    DIRECTION OUTPUT ;
    USE SIGNAL ;
    PORT
      LAYER M5 ;
        RECT  9.072 19.356 9.096 19.44 ;
    END
  END o[230]
  PIN o[231]
    DIRECTION OUTPUT ;
    USE SIGNAL ;
    PORT
      LAYER M5 ;
        RECT  9.168 19.356 9.192 19.44 ;
    END
  END o[231]
  PIN o[232]
    DIRECTION OUTPUT ;
    USE SIGNAL ;
    PORT
      LAYER M5 ;
        RECT  9.264 19.356 9.288 19.44 ;
    END
  END o[232]
  PIN o[233]
    DIRECTION OUTPUT ;
    USE SIGNAL ;
    PORT
      LAYER M5 ;
        RECT  9.36 19.356 9.384 19.44 ;
    END
  END o[233]
  PIN o[234]
    DIRECTION OUTPUT ;
    USE SIGNAL ;
    PORT
      LAYER M5 ;
        RECT  9.456 19.356 9.48 19.44 ;
    END
  END o[234]
  PIN o[235]
    DIRECTION OUTPUT ;
    USE SIGNAL ;
    PORT
      LAYER M5 ;
        RECT  9.552 19.356 9.576 19.44 ;
    END
  END o[235]
  PIN o[236]
    DIRECTION OUTPUT ;
    USE SIGNAL ;
    PORT
      LAYER M5 ;
        RECT  9.648 19.356 9.672 19.44 ;
    END
  END o[236]
  PIN o[237]
    DIRECTION OUTPUT ;
    USE SIGNAL ;
    PORT
      LAYER M5 ;
        RECT  9.744 19.356 9.768 19.44 ;
    END
  END o[237]
  PIN o[238]
    DIRECTION OUTPUT ;
    USE SIGNAL ;
    PORT
      LAYER M5 ;
        RECT  9.84 19.356 9.864 19.44 ;
    END
  END o[238]
  PIN o[239]
    DIRECTION OUTPUT ;
    USE SIGNAL ;
    PORT
      LAYER M5 ;
        RECT  9.936 19.356 9.96 19.44 ;
    END
  END o[239]
  PIN o[23]
    DIRECTION OUTPUT ;
    USE SIGNAL ;
    PORT
      LAYER M5 ;
        RECT  29.904 19.356 29.928 19.44 ;
    END
  END o[23]
  PIN o[240]
    DIRECTION OUTPUT ;
    USE SIGNAL ;
    PORT
      LAYER M5 ;
        RECT  10.032 19.356 10.056 19.44 ;
    END
  END o[240]
  PIN o[241]
    DIRECTION OUTPUT ;
    USE SIGNAL ;
    PORT
      LAYER M5 ;
        RECT  10.128 19.356 10.152 19.44 ;
    END
  END o[241]
  PIN o[242]
    DIRECTION OUTPUT ;
    USE SIGNAL ;
    PORT
      LAYER M5 ;
        RECT  10.224 19.356 10.248 19.44 ;
    END
  END o[242]
  PIN o[243]
    DIRECTION OUTPUT ;
    USE SIGNAL ;
    PORT
      LAYER M5 ;
        RECT  10.32 19.356 10.344 19.44 ;
    END
  END o[243]
  PIN o[244]
    DIRECTION OUTPUT ;
    USE SIGNAL ;
    PORT
      LAYER M5 ;
        RECT  10.416 19.356 10.44 19.44 ;
    END
  END o[244]
  PIN o[245]
    DIRECTION OUTPUT ;
    USE SIGNAL ;
    PORT
      LAYER M5 ;
        RECT  10.512 19.356 10.536 19.44 ;
    END
  END o[245]
  PIN o[246]
    DIRECTION OUTPUT ;
    USE SIGNAL ;
    PORT
      LAYER M5 ;
        RECT  10.608 19.356 10.632 19.44 ;
    END
  END o[246]
  PIN o[247]
    DIRECTION OUTPUT ;
    USE SIGNAL ;
    PORT
      LAYER M5 ;
        RECT  10.704 19.356 10.728 19.44 ;
    END
  END o[247]
  PIN o[248]
    DIRECTION OUTPUT ;
    USE SIGNAL ;
    PORT
      LAYER M5 ;
        RECT  10.8 19.356 10.824 19.44 ;
    END
  END o[248]
  PIN o[249]
    DIRECTION OUTPUT ;
    USE SIGNAL ;
    PORT
      LAYER M5 ;
        RECT  10.896 19.356 10.92 19.44 ;
    END
  END o[249]
  PIN o[24]
    DIRECTION OUTPUT ;
    USE SIGNAL ;
    PORT
      LAYER M5 ;
        RECT  30 19.356 30.024 19.44 ;
    END
  END o[24]
  PIN o[250]
    DIRECTION OUTPUT ;
    USE SIGNAL ;
    PORT
      LAYER M5 ;
        RECT  10.992 19.356 11.016 19.44 ;
    END
  END o[250]
  PIN o[251]
    DIRECTION OUTPUT ;
    USE SIGNAL ;
    PORT
      LAYER M5 ;
        RECT  11.088 19.356 11.112 19.44 ;
    END
  END o[251]
  PIN o[252]
    DIRECTION OUTPUT ;
    USE SIGNAL ;
    PORT
      LAYER M5 ;
        RECT  11.184 19.356 11.208 19.44 ;
    END
  END o[252]
  PIN o[253]
    DIRECTION OUTPUT ;
    USE SIGNAL ;
    PORT
      LAYER M5 ;
        RECT  11.28 19.356 11.304 19.44 ;
    END
  END o[253]
  PIN o[254]
    DIRECTION OUTPUT ;
    USE SIGNAL ;
    PORT
      LAYER M5 ;
        RECT  11.376 19.356 11.4 19.44 ;
    END
  END o[254]
  PIN o[255]
    DIRECTION OUTPUT ;
    USE SIGNAL ;
    PORT
      LAYER M5 ;
        RECT  11.472 19.356 11.496 19.44 ;
    END
  END o[255]
  PIN o[256]
    DIRECTION OUTPUT ;
    USE SIGNAL ;
    PORT
      LAYER M5 ;
        RECT  5.904 19.356 5.928 19.44 ;
    END
  END o[256]
  PIN o[257]
    DIRECTION OUTPUT ;
    USE SIGNAL ;
    PORT
      LAYER M5 ;
        RECT  6 19.356 6.024 19.44 ;
    END
  END o[257]
  PIN o[258]
    DIRECTION OUTPUT ;
    USE SIGNAL ;
    PORT
      LAYER M5 ;
        RECT  6.096 19.356 6.12 19.44 ;
    END
  END o[258]
  PIN o[259]
    DIRECTION OUTPUT ;
    USE SIGNAL ;
    PORT
      LAYER M5 ;
        RECT  6.192 19.356 6.216 19.44 ;
    END
  END o[259]
  PIN o[25]
    DIRECTION OUTPUT ;
    USE SIGNAL ;
    PORT
      LAYER M5 ;
        RECT  30.096 19.356 30.12 19.44 ;
    END
  END o[25]
  PIN o[260]
    DIRECTION OUTPUT ;
    USE SIGNAL ;
    PORT
      LAYER M5 ;
        RECT  6.288 19.356 6.312 19.44 ;
    END
  END o[260]
  PIN o[261]
    DIRECTION OUTPUT ;
    USE SIGNAL ;
    PORT
      LAYER M5 ;
        RECT  6.384 19.356 6.408 19.44 ;
    END
  END o[261]
  PIN o[262]
    DIRECTION OUTPUT ;
    USE SIGNAL ;
    PORT
      LAYER M5 ;
        RECT  6.48 19.356 6.504 19.44 ;
    END
  END o[262]
  PIN o[263]
    DIRECTION OUTPUT ;
    USE SIGNAL ;
    PORT
      LAYER M5 ;
        RECT  6.576 19.356 6.6 19.44 ;
    END
  END o[263]
  PIN o[264]
    DIRECTION OUTPUT ;
    USE SIGNAL ;
    PORT
      LAYER M5 ;
        RECT  6.672 19.356 6.696 19.44 ;
    END
  END o[264]
  PIN o[265]
    DIRECTION OUTPUT ;
    USE SIGNAL ;
    PORT
      LAYER M5 ;
        RECT  6.768 19.356 6.792 19.44 ;
    END
  END o[265]
  PIN o[266]
    DIRECTION OUTPUT ;
    USE SIGNAL ;
    PORT
      LAYER M5 ;
        RECT  6.864 19.356 6.888 19.44 ;
    END
  END o[266]
  PIN o[267]
    DIRECTION OUTPUT ;
    USE SIGNAL ;
    PORT
      LAYER M5 ;
        RECT  6.96 19.356 6.984 19.44 ;
    END
  END o[267]
  PIN o[268]
    DIRECTION OUTPUT ;
    USE SIGNAL ;
    PORT
      LAYER M5 ;
        RECT  7.056 19.356 7.08 19.44 ;
    END
  END o[268]
  PIN o[269]
    DIRECTION OUTPUT ;
    USE SIGNAL ;
    PORT
      LAYER M5 ;
        RECT  7.152 19.356 7.176 19.44 ;
    END
  END o[269]
  PIN o[26]
    DIRECTION OUTPUT ;
    USE SIGNAL ;
    PORT
      LAYER M5 ;
        RECT  30.192 19.356 30.216 19.44 ;
    END
  END o[26]
  PIN o[270]
    DIRECTION OUTPUT ;
    USE SIGNAL ;
    PORT
      LAYER M5 ;
        RECT  7.248 19.356 7.272 19.44 ;
    END
  END o[270]
  PIN o[271]
    DIRECTION OUTPUT ;
    USE SIGNAL ;
    PORT
      LAYER M5 ;
        RECT  7.344 19.356 7.368 19.44 ;
    END
  END o[271]
  PIN o[272]
    DIRECTION OUTPUT ;
    USE SIGNAL ;
    PORT
      LAYER M5 ;
        RECT  7.44 19.356 7.464 19.44 ;
    END
  END o[272]
  PIN o[273]
    DIRECTION OUTPUT ;
    USE SIGNAL ;
    PORT
      LAYER M5 ;
        RECT  7.536 19.356 7.56 19.44 ;
    END
  END o[273]
  PIN o[274]
    DIRECTION OUTPUT ;
    USE SIGNAL ;
    PORT
      LAYER M5 ;
        RECT  7.632 19.356 7.656 19.44 ;
    END
  END o[274]
  PIN o[275]
    DIRECTION OUTPUT ;
    USE SIGNAL ;
    PORT
      LAYER M5 ;
        RECT  7.728 19.356 7.752 19.44 ;
    END
  END o[275]
  PIN o[276]
    DIRECTION OUTPUT ;
    USE SIGNAL ;
    PORT
      LAYER M5 ;
        RECT  7.824 19.356 7.848 19.44 ;
    END
  END o[276]
  PIN o[277]
    DIRECTION OUTPUT ;
    USE SIGNAL ;
    PORT
      LAYER M5 ;
        RECT  7.92 19.356 7.944 19.44 ;
    END
  END o[277]
  PIN o[278]
    DIRECTION OUTPUT ;
    USE SIGNAL ;
    PORT
      LAYER M5 ;
        RECT  8.016 19.356 8.04 19.44 ;
    END
  END o[278]
  PIN o[279]
    DIRECTION OUTPUT ;
    USE SIGNAL ;
    PORT
      LAYER M5 ;
        RECT  8.112 19.356 8.136 19.44 ;
    END
  END o[279]
  PIN o[27]
    DIRECTION OUTPUT ;
    USE SIGNAL ;
    PORT
      LAYER M5 ;
        RECT  30.288 19.356 30.312 19.44 ;
    END
  END o[27]
  PIN o[280]
    DIRECTION OUTPUT ;
    USE SIGNAL ;
    PORT
      LAYER M5 ;
        RECT  8.208 19.356 8.232 19.44 ;
    END
  END o[280]
  PIN o[281]
    DIRECTION OUTPUT ;
    USE SIGNAL ;
    PORT
      LAYER M5 ;
        RECT  8.304 19.356 8.328 19.44 ;
    END
  END o[281]
  PIN o[282]
    DIRECTION OUTPUT ;
    USE SIGNAL ;
    PORT
      LAYER M5 ;
        RECT  8.4 19.356 8.424 19.44 ;
    END
  END o[282]
  PIN o[28]
    DIRECTION OUTPUT ;
    USE SIGNAL ;
    PORT
      LAYER M5 ;
        RECT  30.384 19.356 30.408 19.44 ;
    END
  END o[28]
  PIN o[29]
    DIRECTION OUTPUT ;
    USE SIGNAL ;
    PORT
      LAYER M5 ;
        RECT  30.48 19.356 30.504 19.44 ;
    END
  END o[29]
  PIN o[2]
    DIRECTION OUTPUT ;
    USE SIGNAL ;
    PORT
      LAYER M5 ;
        RECT  27.888 19.356 27.912 19.44 ;
    END
  END o[2]
  PIN o[30]
    DIRECTION OUTPUT ;
    USE SIGNAL ;
    PORT
      LAYER M5 ;
        RECT  30.576 19.356 30.6 19.44 ;
    END
  END o[30]
  PIN o[31]
    DIRECTION OUTPUT ;
    USE SIGNAL ;
    PORT
      LAYER M5 ;
        RECT  30.672 19.356 30.696 19.44 ;
    END
  END o[31]
  PIN o[32]
    DIRECTION OUTPUT ;
    USE SIGNAL ;
    PORT
      LAYER M5 ;
        RECT  24.624 19.356 24.648 19.44 ;
    END
  END o[32]
  PIN o[33]
    DIRECTION OUTPUT ;
    USE SIGNAL ;
    PORT
      LAYER M5 ;
        RECT  24.72 19.356 24.744 19.44 ;
    END
  END o[33]
  PIN o[34]
    DIRECTION OUTPUT ;
    USE SIGNAL ;
    PORT
      LAYER M5 ;
        RECT  24.816 19.356 24.84 19.44 ;
    END
  END o[34]
  PIN o[35]
    DIRECTION OUTPUT ;
    USE SIGNAL ;
    PORT
      LAYER M5 ;
        RECT  24.912 19.356 24.936 19.44 ;
    END
  END o[35]
  PIN o[36]
    DIRECTION OUTPUT ;
    USE SIGNAL ;
    PORT
      LAYER M5 ;
        RECT  25.008 19.356 25.032 19.44 ;
    END
  END o[36]
  PIN o[37]
    DIRECTION OUTPUT ;
    USE SIGNAL ;
    PORT
      LAYER M5 ;
        RECT  25.104 19.356 25.128 19.44 ;
    END
  END o[37]
  PIN o[38]
    DIRECTION OUTPUT ;
    USE SIGNAL ;
    PORT
      LAYER M5 ;
        RECT  25.2 19.356 25.224 19.44 ;
    END
  END o[38]
  PIN o[39]
    DIRECTION OUTPUT ;
    USE SIGNAL ;
    PORT
      LAYER M5 ;
        RECT  25.296 19.356 25.32 19.44 ;
    END
  END o[39]
  PIN o[3]
    DIRECTION OUTPUT ;
    USE SIGNAL ;
    PORT
      LAYER M5 ;
        RECT  27.984 19.356 28.008 19.44 ;
    END
  END o[3]
  PIN o[40]
    DIRECTION OUTPUT ;
    USE SIGNAL ;
    PORT
      LAYER M5 ;
        RECT  25.392 19.356 25.416 19.44 ;
    END
  END o[40]
  PIN o[41]
    DIRECTION OUTPUT ;
    USE SIGNAL ;
    PORT
      LAYER M5 ;
        RECT  25.488 19.356 25.512 19.44 ;
    END
  END o[41]
  PIN o[42]
    DIRECTION OUTPUT ;
    USE SIGNAL ;
    PORT
      LAYER M5 ;
        RECT  25.584 19.356 25.608 19.44 ;
    END
  END o[42]
  PIN o[43]
    DIRECTION OUTPUT ;
    USE SIGNAL ;
    PORT
      LAYER M5 ;
        RECT  25.68 19.356 25.704 19.44 ;
    END
  END o[43]
  PIN o[44]
    DIRECTION OUTPUT ;
    USE SIGNAL ;
    PORT
      LAYER M5 ;
        RECT  25.776 19.356 25.8 19.44 ;
    END
  END o[44]
  PIN o[45]
    DIRECTION OUTPUT ;
    USE SIGNAL ;
    PORT
      LAYER M5 ;
        RECT  25.872 19.356 25.896 19.44 ;
    END
  END o[45]
  PIN o[46]
    DIRECTION OUTPUT ;
    USE SIGNAL ;
    PORT
      LAYER M5 ;
        RECT  25.968 19.356 25.992 19.44 ;
    END
  END o[46]
  PIN o[47]
    DIRECTION OUTPUT ;
    USE SIGNAL ;
    PORT
      LAYER M5 ;
        RECT  26.064 19.356 26.088 19.44 ;
    END
  END o[47]
  PIN o[48]
    DIRECTION OUTPUT ;
    USE SIGNAL ;
    PORT
      LAYER M5 ;
        RECT  26.16 19.356 26.184 19.44 ;
    END
  END o[48]
  PIN o[49]
    DIRECTION OUTPUT ;
    USE SIGNAL ;
    PORT
      LAYER M5 ;
        RECT  26.256 19.356 26.28 19.44 ;
    END
  END o[49]
  PIN o[4]
    DIRECTION OUTPUT ;
    USE SIGNAL ;
    PORT
      LAYER M5 ;
        RECT  28.08 19.356 28.104 19.44 ;
    END
  END o[4]
  PIN o[50]
    DIRECTION OUTPUT ;
    USE SIGNAL ;
    PORT
      LAYER M5 ;
        RECT  26.352 19.356 26.376 19.44 ;
    END
  END o[50]
  PIN o[51]
    DIRECTION OUTPUT ;
    USE SIGNAL ;
    PORT
      LAYER M5 ;
        RECT  26.448 19.356 26.472 19.44 ;
    END
  END o[51]
  PIN o[52]
    DIRECTION OUTPUT ;
    USE SIGNAL ;
    PORT
      LAYER M5 ;
        RECT  26.544 19.356 26.568 19.44 ;
    END
  END o[52]
  PIN o[53]
    DIRECTION OUTPUT ;
    USE SIGNAL ;
    PORT
      LAYER M5 ;
        RECT  26.64 19.356 26.664 19.44 ;
    END
  END o[53]
  PIN o[54]
    DIRECTION OUTPUT ;
    USE SIGNAL ;
    PORT
      LAYER M5 ;
        RECT  26.736 19.356 26.76 19.44 ;
    END
  END o[54]
  PIN o[55]
    DIRECTION OUTPUT ;
    USE SIGNAL ;
    PORT
      LAYER M5 ;
        RECT  26.832 19.356 26.856 19.44 ;
    END
  END o[55]
  PIN o[56]
    DIRECTION OUTPUT ;
    USE SIGNAL ;
    PORT
      LAYER M5 ;
        RECT  26.928 19.356 26.952 19.44 ;
    END
  END o[56]
  PIN o[57]
    DIRECTION OUTPUT ;
    USE SIGNAL ;
    PORT
      LAYER M5 ;
        RECT  27.024 19.356 27.048 19.44 ;
    END
  END o[57]
  PIN o[58]
    DIRECTION OUTPUT ;
    USE SIGNAL ;
    PORT
      LAYER M5 ;
        RECT  27.12 19.356 27.144 19.44 ;
    END
  END o[58]
  PIN o[59]
    DIRECTION OUTPUT ;
    USE SIGNAL ;
    PORT
      LAYER M5 ;
        RECT  27.216 19.356 27.24 19.44 ;
    END
  END o[59]
  PIN o[5]
    DIRECTION OUTPUT ;
    USE SIGNAL ;
    PORT
      LAYER M5 ;
        RECT  28.176 19.356 28.2 19.44 ;
    END
  END o[5]
  PIN o[60]
    DIRECTION OUTPUT ;
    USE SIGNAL ;
    PORT
      LAYER M5 ;
        RECT  27.312 19.356 27.336 19.44 ;
    END
  END o[60]
  PIN o[61]
    DIRECTION OUTPUT ;
    USE SIGNAL ;
    PORT
      LAYER M5 ;
        RECT  27.408 19.356 27.432 19.44 ;
    END
  END o[61]
  PIN o[62]
    DIRECTION OUTPUT ;
    USE SIGNAL ;
    PORT
      LAYER M5 ;
        RECT  27.504 19.356 27.528 19.44 ;
    END
  END o[62]
  PIN o[63]
    DIRECTION OUTPUT ;
    USE SIGNAL ;
    PORT
      LAYER M5 ;
        RECT  27.6 19.356 27.624 19.44 ;
    END
  END o[63]
  PIN o[64]
    DIRECTION OUTPUT ;
    USE SIGNAL ;
    PORT
      LAYER M5 ;
        RECT  21.552 19.356 21.576 19.44 ;
    END
  END o[64]
  PIN o[65]
    DIRECTION OUTPUT ;
    USE SIGNAL ;
    PORT
      LAYER M5 ;
        RECT  21.648 19.356 21.672 19.44 ;
    END
  END o[65]
  PIN o[66]
    DIRECTION OUTPUT ;
    USE SIGNAL ;
    PORT
      LAYER M5 ;
        RECT  21.744 19.356 21.768 19.44 ;
    END
  END o[66]
  PIN o[67]
    DIRECTION OUTPUT ;
    USE SIGNAL ;
    PORT
      LAYER M5 ;
        RECT  21.84 19.356 21.864 19.44 ;
    END
  END o[67]
  PIN o[68]
    DIRECTION OUTPUT ;
    USE SIGNAL ;
    PORT
      LAYER M5 ;
        RECT  21.936 19.356 21.96 19.44 ;
    END
  END o[68]
  PIN o[69]
    DIRECTION OUTPUT ;
    USE SIGNAL ;
    PORT
      LAYER M5 ;
        RECT  22.032 19.356 22.056 19.44 ;
    END
  END o[69]
  PIN o[6]
    DIRECTION OUTPUT ;
    USE SIGNAL ;
    PORT
      LAYER M5 ;
        RECT  28.272 19.356 28.296 19.44 ;
    END
  END o[6]
  PIN o[70]
    DIRECTION OUTPUT ;
    USE SIGNAL ;
    PORT
      LAYER M5 ;
        RECT  22.128 19.356 22.152 19.44 ;
    END
  END o[70]
  PIN o[71]
    DIRECTION OUTPUT ;
    USE SIGNAL ;
    PORT
      LAYER M5 ;
        RECT  22.224 19.356 22.248 19.44 ;
    END
  END o[71]
  PIN o[72]
    DIRECTION OUTPUT ;
    USE SIGNAL ;
    PORT
      LAYER M5 ;
        RECT  22.32 19.356 22.344 19.44 ;
    END
  END o[72]
  PIN o[73]
    DIRECTION OUTPUT ;
    USE SIGNAL ;
    PORT
      LAYER M5 ;
        RECT  22.416 19.356 22.44 19.44 ;
    END
  END o[73]
  PIN o[74]
    DIRECTION OUTPUT ;
    USE SIGNAL ;
    PORT
      LAYER M5 ;
        RECT  22.512 19.356 22.536 19.44 ;
    END
  END o[74]
  PIN o[75]
    DIRECTION OUTPUT ;
    USE SIGNAL ;
    PORT
      LAYER M5 ;
        RECT  22.608 19.356 22.632 19.44 ;
    END
  END o[75]
  PIN o[76]
    DIRECTION OUTPUT ;
    USE SIGNAL ;
    PORT
      LAYER M5 ;
        RECT  22.704 19.356 22.728 19.44 ;
    END
  END o[76]
  PIN o[77]
    DIRECTION OUTPUT ;
    USE SIGNAL ;
    PORT
      LAYER M5 ;
        RECT  22.8 19.356 22.824 19.44 ;
    END
  END o[77]
  PIN o[78]
    DIRECTION OUTPUT ;
    USE SIGNAL ;
    PORT
      LAYER M5 ;
        RECT  22.896 19.356 22.92 19.44 ;
    END
  END o[78]
  PIN o[79]
    DIRECTION OUTPUT ;
    USE SIGNAL ;
    PORT
      LAYER M5 ;
        RECT  22.992 19.356 23.016 19.44 ;
    END
  END o[79]
  PIN o[7]
    DIRECTION OUTPUT ;
    USE SIGNAL ;
    PORT
      LAYER M5 ;
        RECT  28.368 19.356 28.392 19.44 ;
    END
  END o[7]
  PIN o[80]
    DIRECTION OUTPUT ;
    USE SIGNAL ;
    PORT
      LAYER M5 ;
        RECT  23.088 19.356 23.112 19.44 ;
    END
  END o[80]
  PIN o[81]
    DIRECTION OUTPUT ;
    USE SIGNAL ;
    PORT
      LAYER M5 ;
        RECT  23.184 19.356 23.208 19.44 ;
    END
  END o[81]
  PIN o[82]
    DIRECTION OUTPUT ;
    USE SIGNAL ;
    PORT
      LAYER M5 ;
        RECT  23.28 19.356 23.304 19.44 ;
    END
  END o[82]
  PIN o[83]
    DIRECTION OUTPUT ;
    USE SIGNAL ;
    PORT
      LAYER M5 ;
        RECT  23.376 19.356 23.4 19.44 ;
    END
  END o[83]
  PIN o[84]
    DIRECTION OUTPUT ;
    USE SIGNAL ;
    PORT
      LAYER M5 ;
        RECT  23.472 19.356 23.496 19.44 ;
    END
  END o[84]
  PIN o[85]
    DIRECTION OUTPUT ;
    USE SIGNAL ;
    PORT
      LAYER M5 ;
        RECT  23.568 19.356 23.592 19.44 ;
    END
  END o[85]
  PIN o[86]
    DIRECTION OUTPUT ;
    USE SIGNAL ;
    PORT
      LAYER M5 ;
        RECT  23.664 19.356 23.688 19.44 ;
    END
  END o[86]
  PIN o[87]
    DIRECTION OUTPUT ;
    USE SIGNAL ;
    PORT
      LAYER M5 ;
        RECT  23.76 19.356 23.784 19.44 ;
    END
  END o[87]
  PIN o[88]
    DIRECTION OUTPUT ;
    USE SIGNAL ;
    PORT
      LAYER M5 ;
        RECT  23.856 19.356 23.88 19.44 ;
    END
  END o[88]
  PIN o[89]
    DIRECTION OUTPUT ;
    USE SIGNAL ;
    PORT
      LAYER M5 ;
        RECT  23.952 19.356 23.976 19.44 ;
    END
  END o[89]
  PIN o[8]
    DIRECTION OUTPUT ;
    USE SIGNAL ;
    PORT
      LAYER M5 ;
        RECT  28.464 19.356 28.488 19.44 ;
    END
  END o[8]
  PIN o[90]
    DIRECTION OUTPUT ;
    USE SIGNAL ;
    PORT
      LAYER M5 ;
        RECT  24.048 19.356 24.072 19.44 ;
    END
  END o[90]
  PIN o[91]
    DIRECTION OUTPUT ;
    USE SIGNAL ;
    PORT
      LAYER M5 ;
        RECT  24.144 19.356 24.168 19.44 ;
    END
  END o[91]
  PIN o[92]
    DIRECTION OUTPUT ;
    USE SIGNAL ;
    PORT
      LAYER M5 ;
        RECT  24.24 19.356 24.264 19.44 ;
    END
  END o[92]
  PIN o[93]
    DIRECTION OUTPUT ;
    USE SIGNAL ;
    PORT
      LAYER M5 ;
        RECT  24.336 19.356 24.36 19.44 ;
    END
  END o[93]
  PIN o[94]
    DIRECTION OUTPUT ;
    USE SIGNAL ;
    PORT
      LAYER M5 ;
        RECT  24.432 19.356 24.456 19.44 ;
    END
  END o[94]
  PIN o[95]
    DIRECTION OUTPUT ;
    USE SIGNAL ;
    PORT
      LAYER M5 ;
        RECT  24.528 19.356 24.552 19.44 ;
    END
  END o[95]
  PIN o[96]
    DIRECTION OUTPUT ;
    USE SIGNAL ;
    PORT
      LAYER M5 ;
        RECT  15.408 19.356 15.432 19.44 ;
    END
  END o[96]
  PIN o[97]
    DIRECTION OUTPUT ;
    USE SIGNAL ;
    PORT
      LAYER M5 ;
        RECT  15.504 19.356 15.528 19.44 ;
    END
  END o[97]
  PIN o[98]
    DIRECTION OUTPUT ;
    USE SIGNAL ;
    PORT
      LAYER M5 ;
        RECT  15.6 19.356 15.624 19.44 ;
    END
  END o[98]
  PIN o[99]
    DIRECTION OUTPUT ;
    USE SIGNAL ;
    PORT
      LAYER M5 ;
        RECT  15.696 19.356 15.72 19.44 ;
    END
  END o[99]
  PIN o[9]
    DIRECTION OUTPUT ;
    USE SIGNAL ;
    PORT
      LAYER M5 ;
        RECT  28.56 19.356 28.584 19.44 ;
    END
  END o[9]
  PIN rs
    DIRECTION INPUT ;
    USE SIGNAL ;
    PORT
      LAYER M4 ;
        RECT  34.476 10.8 34.56 10.824 ;
    END
  END rs
  PIN VDD
    DIRECTION INOUT ;
    USE POWER ;
    PORT
      LAYER M5 ;
        RECT  29.592 2.151 29.712 17.289 ;
        RECT  24.192 2.151 24.312 17.289 ;
        RECT  18.792 2.151 18.912 17.289 ;
        RECT  13.392 2.151 13.512 17.289 ;
        RECT  7.992 2.151 8.112 17.289 ;
        RECT  2.592 2.151 2.712 17.289 ;
    END
  END VDD
  PIN VSS
    DIRECTION INOUT ;
    USE GROUND ;
    PORT
      LAYER M5 ;
        RECT  29.4 2.137 29.52 17.303 ;
        RECT  24 2.137 24.12 17.303 ;
        RECT  18.6 2.137 18.72 17.303 ;
        RECT  13.2 2.137 13.32 17.303 ;
        RECT  7.8 2.137 7.92 17.303 ;
        RECT  2.4 2.137 2.52 17.303 ;
    END
  END VSS
  OBS
    LAYER RVTN ;
     RECT  2.16 2.16 32.4 2.295 ;
     RECT  2.16 2.565 32.4 2.835 ;
     RECT  2.16 3.105 32.4 3.375 ;
     RECT  2.16 3.645 32.4 3.915 ;
     RECT  2.16 4.185 32.4 4.455 ;
     RECT  2.16 4.725 32.4 4.995 ;
     RECT  2.16 5.265 32.4 5.535 ;
     RECT  2.16 5.805 32.4 6.075 ;
     RECT  2.16 6.345 32.4 6.615 ;
     RECT  2.16 6.885 32.4 7.155 ;
     RECT  2.16 7.425 32.4 7.695 ;
     RECT  2.16 7.965 32.4 8.235 ;
     RECT  2.16 8.505 32.4 8.775 ;
     RECT  2.16 9.045 32.4 9.315 ;
     RECT  2.16 9.585 32.4 9.855 ;
     RECT  2.16 10.125 32.4 10.395 ;
     RECT  2.16 10.665 32.4 10.935 ;
     RECT  2.16 11.205 32.4 11.475 ;
     RECT  2.16 11.745 32.4 12.015 ;
     RECT  2.16 12.285 32.4 12.555 ;
     RECT  2.16 12.825 32.4 13.095 ;
     RECT  2.16 13.365 32.4 13.635 ;
     RECT  2.16 13.905 32.4 14.175 ;
     RECT  2.16 14.445 32.4 14.715 ;
     RECT  2.16 14.985 32.4 15.255 ;
     RECT  2.16 15.525 32.4 15.795 ;
     RECT  2.16 16.065 32.4 16.335 ;
     RECT  2.16 16.605 32.4 16.875 ;
     RECT  2.16 17.145 32.4 17.28 ;
    LAYER RVTP ;
     RECT  2.16 2.295 32.4 2.565 ;
     RECT  2.16 2.835 32.4 3.105 ;
     RECT  2.16 3.375 32.4 3.645 ;
     RECT  2.16 3.915 32.4 4.185 ;
     RECT  2.16 4.455 32.4 4.725 ;
     RECT  2.16 4.995 32.4 5.265 ;
     RECT  2.16 5.535 32.4 5.805 ;
     RECT  2.16 6.075 32.4 6.345 ;
     RECT  2.16 6.615 32.4 6.885 ;
     RECT  2.16 7.155 32.4 7.425 ;
     RECT  2.16 7.695 32.4 7.965 ;
     RECT  2.16 8.235 32.4 8.505 ;
     RECT  2.16 8.775 32.4 9.045 ;
     RECT  2.16 9.315 32.4 9.585 ;
     RECT  2.16 9.855 32.4 10.125 ;
     RECT  2.16 10.395 32.4 10.665 ;
     RECT  2.16 10.935 32.4 11.205 ;
     RECT  2.16 11.475 32.4 11.745 ;
     RECT  2.16 12.015 32.4 12.285 ;
     RECT  2.16 12.555 32.4 12.825 ;
     RECT  2.16 13.095 32.4 13.365 ;
     RECT  2.16 13.635 32.4 13.905 ;
     RECT  2.16 14.175 32.4 14.445 ;
     RECT  2.16 14.715 32.4 14.985 ;
     RECT  2.16 15.255 32.4 15.525 ;
     RECT  2.16 15.795 32.4 16.065 ;
     RECT  2.16 16.335 32.4 16.605 ;
     RECT  2.16 16.875 32.4 17.145 ;
    LAYER M1 ;
     RECT  2.16 2.151 32.4 17.289 ;
    LAYER M2 ;
     RECT  1.219 3.042 1.327 3.06 ;
     RECT  1.399 7.092 1.507 7.11 ;
     RECT  1.327 3.042 1.723 3.402 ;
     RECT  1.723 3.042 1.975 4.14 ;
     RECT  1.975 3.042 2.16 4.41 ;
     RECT  1.507 7.092 2.16 7.65 ;
     RECT  2.16 2.151 5.575 17.289 ;
     RECT  5.575 1.998 9.715 17.289 ;
     RECT  9.715 1.926 12.919 17.289 ;
     RECT  12.883 1.116 13.387 1.134 ;
     RECT  12.919 1.881 13.387 17.289 ;
     RECT  13.387 1.116 13.783 17.289 ;
     RECT  13.783 0.846 16.447 17.289 ;
     RECT  16.447 0.576 18.211 17.289 ;
     RECT  18.211 0.036 19.391 17.289 ;
     RECT  19.391 0.846 23.099 17.289 ;
     RECT  23.099 0.882 24.251 17.289 ;
     RECT  24.251 0.918 24.539 17.289 ;
     RECT  19.391 0.036 25.007 0.054 ;
     RECT  25.555 18.774 26.087 18.792 ;
     RECT  24.539 1.116 28.823 17.289 ;
     RECT  28.823 1.692 29.831 17.289 ;
     RECT  29.831 2.151 32.4 17.289 ;
     RECT  32.4 12.528 32.423 15.894 ;
     RECT  32.423 15.732 32.495 15.894 ;
     RECT  32.4 16.884 32.495 16.974 ;
     RECT  32.4 7.236 32.567 7.344 ;
     RECT  32.567 7.236 32.603 7.254 ;
     RECT  32.423 12.528 32.603 14.94 ;
     RECT  32.4 9.594 32.747 11.394 ;
     RECT  32.747 9.594 32.783 9.612 ;
     RECT  32.603 12.528 32.855 13.464 ;
     RECT  32.747 10.404 32.891 11.394 ;
     RECT  32.495 15.876 32.891 15.894 ;
     RECT  32.855 13.446 32.963 13.464 ;
     RECT  32.603 14.841 32.963 14.94 ;
     RECT  32.963 14.841 33.035 14.859 ;
     RECT  32.891 10.404 33.323 10.692 ;
     RECT  32.495 16.884 33.611 16.902 ;
     RECT  33.323 10.404 33.647 10.422 ;
     RECT  32.855 12.528 33.647 12.546 ;
    LAYER M3 ;
     RECT  24.984 0.031 25.002 0.043 ;
     RECT  19.368 0.043 19.386 0.091 ;
     RECT  24.804 0.043 25.002 0.091 ;
     RECT  20.52 0.091 20.538 0.139 ;
     RECT  21.456 0.091 21.762 0.139 ;
     RECT  23.076 0.091 25.002 0.139 ;
     RECT  26.172 0.091 26.19 0.139 ;
     RECT  27 0.091 27.378 0.139 ;
     RECT  23.004 0.139 25.074 0.187 ;
     RECT  19.368 0.091 19.53 0.235 ;
     RECT  20.448 0.139 20.538 0.235 ;
     RECT  13.644 0.091 13.662 0.269 ;
     RECT  21.384 0.139 21.762 0.269 ;
     RECT  22.896 0.187 25.074 0.317 ;
     RECT  21.456 0.269 21.762 0.571 ;
     RECT  23.076 0.317 25.074 0.571 ;
     RECT  25.884 0.139 26.19 0.571 ;
     RECT  27 0.139 27.666 0.571 ;
     RECT  19.368 0.235 20.538 0.599 ;
     RECT  23.076 0.571 25.11 0.869 ;
     RECT  15.948 0.571 16.47 0.877 ;
     RECT  15.408 0.877 16.47 0.913 ;
     RECT  17.316 0.187 17.334 0.913 ;
     RECT  23.184 0.869 25.11 0.941 ;
     RECT  25.884 0.571 28.566 1.111 ;
     RECT  19.512 0.599 20.538 1.336 ;
     RECT  21.456 0.571 22.338 1.336 ;
     RECT  13.788 0.841 13.806 1.387 ;
     RECT  15.408 0.913 17.334 1.453 ;
     RECT  15.372 1.453 17.334 1.489 ;
     RECT  12.888 1.111 12.906 1.606 ;
     RECT  13.788 1.387 14.346 1.606 ;
     RECT  24.912 0.941 25.11 1.627 ;
     RECT  25.884 1.111 28.818 1.627 ;
     RECT  3.996 0.571 4.014 1.723 ;
     RECT  5.688 0.091 5.706 1.723 ;
     RECT  6.84 0.571 6.858 1.723 ;
     RECT  12.888 1.606 14.346 1.723 ;
     RECT  15.3 1.489 17.334 1.723 ;
     RECT  18.216 0.031 18.234 1.723 ;
     RECT  19.512 1.336 22.338 1.723 ;
     RECT  23.184 0.941 24.138 1.723 ;
     RECT  24.912 1.627 28.818 1.723 ;
     RECT  2.304 1.723 9.99 1.771 ;
     RECT  11.088 1.723 18.45 1.771 ;
     RECT  19.512 1.723 29.034 1.771 ;
     RECT  2.304 1.771 29.034 1.819 ;
     RECT  29.808 1.687 29.826 1.915 ;
     RECT  2.196 1.819 29.034 2.143 ;
     RECT  29.808 1.915 30.222 2.143 ;
     RECT  2.196 2.143 30.222 2.299 ;
     RECT  2.196 2.299 30.618 2.335 ;
     RECT  31.392 2.227 31.41 2.335 ;
     RECT  2.196 2.335 31.41 2.489 ;
     RECT  2.196 2.489 31.374 2.875 ;
     RECT  1.728 2.875 31.374 2.923 ;
     RECT  1.224 2.923 31.374 3.065 ;
     RECT  1.332 3.065 31.374 3.407 ;
     RECT  1.728 3.407 31.374 3.721 ;
     RECT  1.728 3.721 31.554 4.145 ;
     RECT  1.98 4.145 31.554 4.261 ;
     RECT  1.98 4.261 31.59 4.415 ;
     RECT  2.268 4.415 31.59 4.801 ;
     RECT  2.268 4.801 31.734 5.225 ;
     RECT  2.304 5.225 31.734 5.495 ;
     RECT  2.34 5.495 31.734 6.232 ;
     RECT  2.34 6.232 31.842 6.269 ;
     RECT  1.404 5.707 1.422 7.115 ;
     RECT  2.34 6.269 31.734 7.231 ;
     RECT  32.58 7.231 32.598 7.321 ;
     RECT  1.512 7.435 1.53 7.655 ;
     RECT  2.304 7.231 31.734 8.275 ;
     RECT  32.544 7.321 32.598 8.275 ;
     RECT  2.304 8.275 32.598 9.589 ;
     RECT  2.304 9.589 32.778 10.669 ;
     RECT  33.624 10.399 33.642 10.669 ;
     RECT  2.304 10.669 33.642 10.769 ;
     RECT  2.34 10.769 33.642 10.829 ;
     RECT  2.34 10.829 33.318 12.523 ;
     RECT  2.34 12.523 33.642 15.215 ;
     RECT  2.415 15.215 33.642 16.799 ;
     RECT  4.392 16.799 4.41 16.835 ;
     RECT  2.415 16.799 3.618 16.907 ;
     RECT  2.415 16.907 3.474 16.943 ;
     RECT  5.184 16.799 33.642 16.979 ;
     RECT  2.415 16.943 2.697 17.027 ;
     RECT  5.364 16.979 33.642 17.069 ;
     RECT  15.552 17.069 33.642 17.105 ;
     RECT  5.58 17.069 14.382 17.117 ;
     RECT  32.148 17.105 33.642 17.117 ;
     RECT  15.552 17.105 30.762 17.141 ;
     RECT  2.415 17.027 2.505 17.297 ;
     RECT  5.58 17.117 14.166 17.645 ;
     RECT  15.552 17.141 30.654 17.645 ;
     RECT  32.148 17.117 33.606 17.645 ;
     RECT  6.552 17.645 13.842 17.693 ;
     RECT  17.928 17.645 28.458 17.693 ;
     RECT  32.148 17.645 33.318 17.693 ;
     RECT  6.552 17.693 10.962 18.221 ;
     RECT  12.24 17.693 13.734 18.221 ;
     RECT  18.396 17.693 26.838 18.221 ;
     RECT  6.552 18.221 7.974 18.269 ;
     RECT  9.252 18.221 10.71 18.269 ;
     RECT  15.552 17.645 16.47 18.269 ;
     RECT  21.276 18.221 26.082 18.269 ;
     RECT  29.34 17.645 30.654 18.269 ;
     RECT  21.276 18.269 22.194 18.317 ;
     RECT  32.256 17.693 33.318 18.475 ;
     RECT  18.396 18.221 20.538 18.749 ;
     RECT  29.34 18.269 29.574 18.749 ;
     RECT  5.58 17.645 5.598 18.797 ;
     RECT  6.66 18.269 6.678 18.797 ;
     RECT  7.524 18.269 7.794 18.797 ;
     RECT  9.252 18.269 9.27 18.797 ;
     RECT  12.24 18.221 13.374 18.797 ;
     RECT  15.588 18.269 16.47 18.797 ;
     RECT  18.504 18.749 18.522 18.797 ;
     RECT  19.332 18.749 20.538 18.797 ;
     RECT  22.932 18.269 26.082 18.797 ;
     RECT  29.556 18.749 29.574 18.797 ;
     RECT  15.588 18.797 15.606 18.845 ;
     RECT  19.584 18.797 20.538 18.845 ;
     RECT  22.932 18.797 23.238 18.845 ;
     RECT  25.632 18.797 26.082 18.845 ;
     RECT  30.636 18.269 30.654 18.845 ;
     RECT  24.336 18.797 24.462 19.181 ;
     RECT  26.82 18.221 26.838 19.195 ;
     RECT  21.276 18.317 21.654 19.229 ;
     RECT  21.276 19.229 21.546 19.277 ;
     RECT  27.648 17.693 28.458 19.277 ;
     RECT  31.896 18.475 33.318 19.277 ;
     RECT  30.96 19.099 30.978 19.291 ;
     RECT  31.896 19.277 31.914 19.291 ;
     RECT  7.776 18.797 7.794 19.325 ;
     RECT  10.152 18.269 10.71 19.325 ;
     RECT  12.312 18.797 13.374 19.325 ;
     RECT  19.836 18.845 20.43 19.325 ;
     RECT  21.276 19.277 21.294 19.325 ;
     RECT  24.336 19.181 24.354 19.325 ;
     RECT  25.632 18.845 25.65 19.325 ;
     RECT  26.46 19.195 26.838 19.325 ;
     RECT  27.648 19.277 27.666 19.325 ;
     RECT  28.44 19.277 28.458 19.325 ;
     RECT  30.96 19.291 31.914 19.325 ;
     RECT  32.688 19.277 33.318 19.325 ;
     RECT  26.82 19.325 26.838 19.421 ;
     RECT  31.32 19.325 31.338 19.421 ;
    LAYER M4 ;
     RECT  0.709 1.728 0.805 1.752 ;
     RECT  0.805 1.728 0.901 2.328 ;
     RECT  0.997 4.56 1.093 4.584 ;
     RECT  0.901 1.728 1.169 2.904 ;
     RECT  1.169 1.728 1.252 2.952 ;
     RECT  1.093 4.56 1.349 4.776 ;
     RECT  1.349 4.56 1.433 5.736 ;
     RECT  1.433 4.56 1.925 5.496 ;
     RECT  1.252 1.728 2.053 3 ;
     RECT  1.925 3.984 2.053 5.496 ;
     RECT  2.053 1.728 2.408 5.496 ;
     RECT  1.457 7.44 2.408 7.464 ;
     RECT  2.408 1.728 2.512 17.292 ;
     RECT  2.512 1.728 2.704 17.022 ;
     RECT  2.629 0.144 2.819 0.168 ;
     RECT  2.704 1.728 2.873 2.232 ;
     RECT  2.704 13.344 2.953 16.584 ;
     RECT  2.953 15.984 3.011 16.584 ;
     RECT  2.704 3.888 3.017 4.488 ;
     RECT  3.011 15.984 3.089 16.008 ;
     RECT  2.704 8.256 3.161 8.76 ;
     RECT  3.017 3.984 3.305 4.488 ;
     RECT  2.704 6.288 3.449 6.312 ;
     RECT  2.873 1.728 3.869 1.896 ;
     RECT  3.941 0.576 4.025 0.6 ;
     RECT  2.704 10.08 4.205 10.872 ;
     RECT  4.205 10.416 4.237 10.872 ;
     RECT  2.953 13.344 4.237 14.856 ;
     RECT  3.161 8.256 4.261 8.472 ;
     RECT  3.305 4.464 4.309 4.488 ;
     RECT  4.237 10.416 4.321 14.856 ;
     RECT  3.733 6.576 4.417 6.6 ;
     RECT  4.321 13.344 4.453 14.856 ;
     RECT  3.869 1.728 4.645 1.992 ;
     RECT  4.417 6.384 4.777 6.6 ;
     RECT  4.261 7.776 4.777 8.472 ;
     RECT  4.309 4.464 4.885 5.112 ;
     RECT  4.885 4.368 4.921 5.112 ;
     RECT  4.645 1.728 4.933 2.328 ;
     RECT  4.933 1.728 5.029 2.904 ;
     RECT  4.921 3.936 5.029 5.112 ;
     RECT  4.777 7.632 5.065 8.472 ;
     RECT  4.777 6.24 5.101 6.6 ;
     RECT  5.065 7.632 5.101 8.52 ;
     RECT  5.029 1.728 5.137 5.112 ;
     RECT  5.101 6.24 5.137 8.52 ;
     RECT  5.137 1.728 5.213 8.52 ;
     RECT  5.213 2.88 5.285 8.52 ;
     RECT  4.321 10.416 5.605 12.216 ;
     RECT  4.453 13.344 5.605 15.72 ;
     RECT  5.605 10.416 5.677 15.72 ;
     RECT  5.677 0.096 5.761 0.12 ;
     RECT  5.677 9.792 5.785 15.72 ;
     RECT  4.381 16.8 5.785 16.824 ;
     RECT  5.285 3.6 5.893 8.52 ;
     RECT  5.785 9.792 5.989 16.824 ;
     RECT  5.989 9.792 6.373 17.64 ;
     RECT  5.569 18.768 6.373 18.792 ;
     RECT  5.893 3.6 6.397 8.712 ;
     RECT  6.373 9.792 6.437 18.792 ;
     RECT  6.829 0.576 6.913 0.6 ;
     RECT  6.397 3.024 6.949 8.712 ;
     RECT  6.437 9.792 6.949 9.864 ;
     RECT  6.949 3.024 7.237 9.864 ;
     RECT  7.237 2.88 7.405 9.864 ;
     RECT  6.437 11.232 7.405 18.792 ;
     RECT  7.405 2.88 7.429 18.792 ;
     RECT  5.213 1.728 7.621 1.848 ;
     RECT  7.429 2.88 7.705 19.32 ;
     RECT  7.705 19.248 7.805 19.32 ;
     RECT  7.621 1.728 7.808 1.896 ;
     RECT  7.705 2.88 7.808 18.264 ;
     RECT  7.669 0.144 7.955 0.168 ;
     RECT  7.805 19.248 7.955 19.272 ;
     RECT  7.808 1.728 7.985 18.264 ;
     RECT  7.985 1.728 8.104 18.216 ;
     RECT  8.104 1.728 9.109 9.864 ;
     RECT  8.104 10.944 9.109 18.216 ;
     RECT  9.109 1.728 9.137 17.16 ;
     RECT  9.109 18.192 9.241 18.216 ;
     RECT  9.241 18.192 9.325 18.792 ;
     RECT  9.137 1.728 9.731 17.112 ;
     RECT  9.731 14.352 10.172 17.112 ;
     RECT  9.325 18.192 10.364 18.264 ;
     RECT  9.733 19.296 10.364 19.32 ;
     RECT  10.364 18.192 10.649 19.32 ;
     RECT  10.649 19.296 10.721 19.32 ;
     RECT  9.731 1.728 10.789 13.368 ;
     RECT  10.172 14.352 10.789 17.208 ;
     RECT  10.649 18.192 10.973 18.216 ;
     RECT  10.789 1.728 10.981 17.208 ;
     RECT  10.981 1.728 11.795 17.688 ;
     RECT  11.795 1.728 11.987 17.112 ;
     RECT  12.037 19.296 12.229 19.32 ;
     RECT  12.229 18.768 12.312 19.32 ;
     RECT  12.312 18.72 12.485 19.32 ;
     RECT  11.987 1.728 13.208 17.064 ;
     RECT  13.208 1.728 13.237 17.292 ;
     RECT  13.237 1.152 13.285 17.292 ;
     RECT  13.237 0.144 13.477 0.168 ;
     RECT  13.285 1.152 13.477 17.448 ;
     RECT  13.477 0.144 13.532 17.448 ;
     RECT  13.532 0.144 13.618 17.544 ;
     RECT  12.485 19.056 13.619 19.32 ;
     RECT  13.618 0.096 13.661 17.544 ;
     RECT  13.619 19.056 13.661 19.08 ;
     RECT  13.661 0.096 13.667 19.08 ;
     RECT  13.667 0.096 13.717 0.264 ;
     RECT  13.667 1.392 13.745 18.216 ;
     RECT  13.717 0.24 13.763 0.264 ;
     RECT  13.745 1.392 13.853 17.688 ;
     RECT  13.853 1.392 14.221 17.64 ;
     RECT  14.221 1.392 14.428 17.112 ;
     RECT  14.428 1.392 14.867 16.872 ;
     RECT  15.301 0.096 15.397 0.12 ;
     RECT  14.867 1.392 15.397 16.536 ;
     RECT  15.397 18.768 15.541 18.792 ;
     RECT  15.541 18.24 15.577 18.792 ;
     RECT  15.577 18.24 15.731 18.84 ;
     RECT  15.397 0.096 15.941 16.536 ;
     RECT  15.731 18.24 16.261 18.792 ;
     RECT  15.941 0.096 16.301 16.488 ;
     RECT  16.261 18.192 16.345 18.792 ;
     RECT  16.345 18.672 16.445 18.792 ;
     RECT  16.445 18.768 16.481 18.792 ;
     RECT  16.549 17.616 16.613 17.64 ;
     RECT  16.613 17.568 17.017 17.64 ;
     RECT  16.301 0.096 17.317 16.44 ;
     RECT  17.017 17.472 17.317 17.64 ;
     RECT  17.317 0.096 17.797 17.64 ;
     RECT  18.277 18.768 18.341 18.792 ;
     RECT  18.341 18.72 18.421 18.792 ;
     RECT  17.797 0.096 18.803 17.688 ;
     RECT  18.421 18.72 18.908 19.272 ;
     RECT  18.803 0.096 19.187 17.112 ;
     RECT  18.908 18.24 19.324 19.272 ;
     RECT  19.187 0.096 19.357 16.632 ;
     RECT  19.324 18.768 19.525 19.272 ;
     RECT  19.357 0.048 20.189 16.632 ;
     RECT  19.525 18.768 20.368 19.32 ;
     RECT  20.189 15.36 20.369 16.632 ;
     RECT  20.369 16.32 20.437 16.632 ;
     RECT  19.897 17.616 20.437 17.64 ;
     RECT  20.437 16.32 20.645 17.64 ;
     RECT  20.368 18.72 20.645 19.32 ;
     RECT  20.645 16.32 20.729 19.32 ;
     RECT  20.729 16.32 21.089 17.688 ;
     RECT  20.729 18.768 21.305 19.32 ;
     RECT  21.089 16.32 21.541 17.16 ;
     RECT  21.305 18.768 21.557 19.272 ;
     RECT  21.301 14.832 21.661 14.856 ;
     RECT  21.541 15.984 21.661 17.16 ;
     RECT  21.557 18.768 21.665 19.224 ;
     RECT  21.665 18.768 21.683 18.84 ;
     RECT  21.661 14.832 21.805 17.16 ;
     RECT  20.189 0.048 21.877 13.704 ;
     RECT  21.805 14.784 21.877 17.16 ;
     RECT  21.877 0.048 22.025 17.16 ;
     RECT  21.829 18.24 22.451 18.312 ;
     RECT  22.025 0.048 22.547 13.56 ;
     RECT  22.025 14.688 22.661 17.16 ;
     RECT  22.547 1.392 23.173 13.56 ;
     RECT  22.661 14.688 23.173 17.64 ;
     RECT  22.921 18.816 23.557 18.84 ;
     RECT  23.557 18.768 23.941 18.84 ;
     RECT  22.547 0.048 23.965 0.312 ;
     RECT  23.173 1.392 23.965 17.64 ;
     RECT  23.965 0.048 24.083 17.64 ;
     RECT  23.941 18.768 24.365 19.32 ;
     RECT  24.083 1.728 24.509 17.64 ;
     RECT  24.365 18.768 24.515 19.272 ;
     RECT  24.515 18.768 24.613 18.792 ;
     RECT  24.083 0.048 24.833 0.312 ;
     RECT  24.833 0.096 25.057 0.312 ;
     RECT  25.057 0.144 25.081 0.312 ;
     RECT  25.081 0.144 25.165 0.6 ;
     RECT  24.509 1.728 25.193 17.208 ;
     RECT  25.165 0.144 25.331 0.216 ;
     RECT  25.193 10.704 25.523 17.208 ;
     RECT  24.613 18.192 25.573 18.792 ;
     RECT  25.523 14.592 25.589 17.208 ;
     RECT  25.589 14.784 25.649 17.208 ;
     RECT  25.573 18.192 25.649 19.32 ;
     RECT  25.523 10.704 25.66 13.128 ;
     RECT  25.193 1.728 25.693 9.672 ;
     RECT  25.66 10.704 25.811 13.08 ;
     RECT  25.331 0.144 26.161 0.168 ;
     RECT  25.693 1.632 26.345 9.672 ;
     RECT  25.811 10.704 26.389 12.552 ;
     RECT  26.345 1.632 26.483 8.472 ;
     RECT  26.345 9.648 26.525 9.672 ;
     RECT  26.483 1.68 26.675 8.232 ;
     RECT  26.161 0.096 26.773 0.168 ;
     RECT  25.649 14.784 26.809 19.32 ;
     RECT  26.675 1.68 26.921 7.992 ;
     RECT  26.773 0.096 26.963 0.6 ;
     RECT  26.389 12.528 27.241 12.552 ;
     RECT  26.389 10.704 27.245 11.544 ;
     RECT  26.921 1.68 27.251 6.744 ;
     RECT  27.241 12.528 27.395 13.08 ;
     RECT  26.921 7.968 27.569 7.992 ;
     RECT  26.963 0.096 27.635 0.168 ;
     RECT  27.245 10.704 27.677 10.824 ;
     RECT  26.809 14.784 27.685 19.416 ;
     RECT  27.251 1.728 27.961 6.744 ;
     RECT  27.589 13.104 27.973 13.128 ;
     RECT  27.685 14.256 27.973 19.416 ;
     RECT  27.635 0.144 28.115 0.168 ;
     RECT  27.973 13.104 28.145 19.416 ;
     RECT  27.961 1.728 28.433 6.792 ;
     RECT  28.249 0.576 28.621 0.6 ;
     RECT  28.433 1.728 29.089 6.36 ;
     RECT  28.145 13.344 29.365 19.416 ;
     RECT  29.089 1.92 29.408 6.36 ;
     RECT  27.677 10.704 29.408 10.728 ;
     RECT  29.365 12.528 29.408 19.416 ;
     RECT  29.408 1.92 29.704 19.416 ;
     RECT  29.704 3.936 29.765 6.072 ;
     RECT  29.704 14.688 29.873 19.416 ;
     RECT  29.765 5.952 29.909 6.072 ;
     RECT  29.704 1.92 30.017 2.28 ;
     RECT  29.873 18.24 30.035 19.416 ;
     RECT  30.017 1.92 30.197 2.088 ;
     RECT  29.873 14.688 30.227 17.16 ;
     RECT  30.197 1.92 30.233 1.944 ;
     RECT  29.765 3.936 30.233 4.968 ;
     RECT  29.704 12.528 30.659 13.704 ;
     RECT  30.227 14.688 30.701 17.016 ;
     RECT  30.233 4.512 30.755 4.536 ;
     RECT  30.659 12.528 31.043 13.656 ;
     RECT  29.909 5.952 31.057 5.976 ;
     RECT  31.057 5.952 31.165 6.264 ;
     RECT  30.701 14.688 31.187 16.584 ;
     RECT  31.043 12.528 31.201 13.512 ;
     RECT  31.165 5.664 31.249 6.264 ;
     RECT  30.035 18.48 31.349 19.416 ;
     RECT  29.704 10.704 31.453 10.728 ;
     RECT  31.201 12 31.453 13.512 ;
     RECT  31.187 14.976 31.465 16.584 ;
     RECT  31.453 10.704 31.475 13.512 ;
     RECT  31.477 3.936 31.565 3.96 ;
     RECT  31.475 10.704 31.637 13.368 ;
     RECT  31.637 10.704 31.669 10.824 ;
     RECT  31.669 10.272 31.889 10.824 ;
     RECT  31.889 10.272 31.925 10.728 ;
     RECT  31.465 14.976 31.925 16.536 ;
     RECT  31.249 6.24 31.955 6.264 ;
     RECT  31.925 15.744 32.051 16.536 ;
     RECT  31.349 18.48 32.137 19.32 ;
     RECT  31.637 11.808 32.249 13.368 ;
     RECT  32.249 11.808 32.339 11.832 ;
     RECT  32.249 13.344 32.435 13.368 ;
     RECT  32.051 16.416 32.573 16.536 ;
     RECT  32.573 16.464 32.753 16.536 ;
     RECT  32.753 16.512 32.785 16.536 ;
     RECT  32.785 16.512 32.941 16.632 ;
     RECT  32.941 16.56 33.001 16.632 ;
     RECT  32.137 17.664 33.107 19.32 ;
     RECT  33.001 16.56 33.203 16.68 ;
     RECT  33.107 19.296 33.329 19.32 ;
     RECT  33.107 17.664 33.395 18.264 ;
     RECT  33.203 16.608 33.491 16.68 ;
     RECT  33.491 16.656 33.577 16.68 ;
     RECT  33.577 16.656 33.587 17.64 ;
     RECT  31.925 10.704 33.613 10.728 ;
     RECT  33.587 17.088 33.683 17.64 ;
     RECT  33.683 17.616 33.779 17.64 ;
     RECT  33.613 10.704 34.524 10.824 ;
    LAYER M5 ;
     RECT  0.72 0.016 29.064 1.763 ;
     RECT  0.816 1.763 29.064 1.811 ;
     RECT  0.816 1.811 25.416 1.859 ;
     RECT  22.896 1.859 24.456 1.907 ;
     RECT  6.672 1.859 21.864 1.955 ;
     RECT  0.816 1.859 5.256 2.003 ;
     RECT  12.816 1.955 21.864 2.099 ;
     RECT  26.64 1.811 29.064 2.137 ;
     RECT  26.64 2.137 29.52 2.151 ;
     RECT  6.672 1.955 11.784 2.243 ;
     RECT  26.64 2.151 29.712 2.243 ;
     RECT  0.816 2.003 3.336 2.339 ;
     RECT  0.912 2.339 3.336 2.915 ;
     RECT  6.672 2.243 10.44 2.915 ;
     RECT  11.664 2.243 11.784 2.915 ;
     RECT  11.76 2.915 11.784 2.963 ;
     RECT  13.008 2.099 21.864 3.059 ;
     RECT  4.56 2.003 5.256 3.155 ;
     RECT  13.008 3.059 19.944 3.157 ;
     RECT  4.56 3.155 5.112 3.443 ;
     RECT  7.68 2.915 10.44 3.443 ;
     RECT  20.976 3.059 21.864 3.443 ;
     RECT  21.072 3.443 21.864 3.491 ;
     RECT  26.64 2.243 27.816 3.587 ;
     RECT  23.28 1.907 24.312 3.827 ;
     RECT  6.672 2.915 6.696 3.925 ;
     RECT  7.68 3.443 9.528 4.019 ;
     RECT  7.8 4.019 9.528 4.067 ;
     RECT  6.528 3.925 6.696 4.115 ;
     RECT  4.56 3.443 5.064 4.501 ;
     RECT  6.528 4.115 6.552 4.501 ;
     RECT  31.488 3.925 31.512 4.501 ;
     RECT  1.008 2.915 3.336 4.595 ;
     RECT  4.56 4.501 6.552 4.595 ;
     RECT  21.168 3.491 21.864 4.595 ;
     RECT  12.672 3.157 19.944 4.645 ;
     RECT  4.896 4.595 6.552 4.691 ;
     RECT  10.752 4.453 10.776 4.693 ;
     RECT  21.84 4.595 21.864 4.739 ;
     RECT  12.672 4.645 20.616 4.741 ;
     RECT  1.104 4.595 3.336 4.787 ;
     RECT  10.752 4.693 11.496 4.835 ;
     RECT  24 3.827 24.312 4.837 ;
     RECT  10.848 4.835 11.496 4.885 ;
     RECT  12.528 4.741 20.616 4.885 ;
     RECT  10.848 4.885 20.616 4.931 ;
     RECT  10.848 4.931 14.376 5.075 ;
     RECT  12.384 5.075 14.376 5.123 ;
     RECT  24 4.837 24.936 5.125 ;
     RECT  4.896 4.691 5.832 5.507 ;
     RECT  10.848 5.075 10.872 5.603 ;
     RECT  26.64 3.587 27.48 5.653 ;
     RECT  1.392 4.787 3.336 5.747 ;
     RECT  15.552 4.931 20.616 5.747 ;
     RECT  24 5.125 25.032 5.749 ;
     RECT  12.528 5.123 14.376 5.795 ;
     RECT  15.552 5.747 20.184 6.035 ;
     RECT  26.64 5.653 28.2 6.085 ;
     RECT  29.4 2.243 29.712 6.085 ;
     RECT  4.896 5.507 5.064 6.229 ;
     RECT  15.552 6.035 15.576 6.229 ;
     RECT  30.72 4.501 31.512 6.229 ;
     RECT  24 5.749 25.656 6.275 ;
     RECT  1.488 5.747 3.336 6.323 ;
     RECT  16.848 6.035 20.184 6.467 ;
     RECT  12.528 5.795 13.512 6.565 ;
     RECT  20.16 6.467 20.184 6.709 ;
     RECT  21.648 5.797 21.672 6.709 ;
     RECT  6.528 6.661 6.552 6.803 ;
     RECT  7.8 4.067 8.424 6.805 ;
     RECT  10.08 6.229 10.104 6.805 ;
     RECT  14.88 6.229 15.576 7.045 ;
     RECT  16.848 6.467 19.128 7.045 ;
     RECT  20.16 6.709 21.672 7.091 ;
     RECT  12 6.565 13.512 7.381 ;
     RECT  1.488 6.323 3 7.475 ;
     RECT  24 6.275 24.936 7.717 ;
     RECT  4.8 6.229 5.064 7.765 ;
     RECT  24 7.717 25.032 7.957 ;
     RECT  23.712 7.957 25.032 8.099 ;
     RECT  6.528 7.813 6.552 8.243 ;
     RECT  26.64 6.085 29.712 8.243 ;
     RECT  14.88 7.045 19.128 8.485 ;
     RECT  7.8 6.805 10.104 8.533 ;
     RECT  20.16 7.091 21.144 8.533 ;
     RECT  11.952 7.381 13.512 8.725 ;
     RECT  14.544 8.485 19.128 8.725 ;
     RECT  20.16 8.533 21.768 8.963 ;
     RECT  20.16 8.963 20.184 9.251 ;
     RECT  21.648 8.963 21.768 9.347 ;
     RECT  6.96 8.533 10.104 9.491 ;
     RECT  2.4 7.475 3 10.069 ;
     RECT  4.272 7.765 5.064 10.069 ;
     RECT  7.296 9.491 10.104 10.261 ;
     RECT  11.952 8.725 19.128 10.261 ;
     RECT  2.4 10.069 5.064 10.883 ;
     RECT  6.192 10.405 6.216 10.883 ;
     RECT  7.296 10.261 19.128 10.883 ;
     RECT  21.648 9.347 21.672 10.885 ;
     RECT  7.296 10.883 18.912 10.931 ;
     RECT  21.264 10.885 21.672 11.365 ;
     RECT  22.848 11.269 22.872 11.365 ;
     RECT  30.72 6.229 31.944 11.797 ;
     RECT  7.296 10.931 10.248 11.893 ;
     RECT  11.952 10.931 18.912 11.893 ;
     RECT  20.304 11.365 22.872 11.941 ;
     RECT  24 8.099 25.032 11.941 ;
     RECT  26.448 8.437 26.472 11.941 ;
     RECT  7.296 11.893 18.912 12.517 ;
     RECT  26.352 11.941 26.472 12.517 ;
     RECT  27.456 8.243 29.712 12.517 ;
     RECT  30.72 11.797 32.328 12.517 ;
     RECT  4.272 10.883 5.064 12.563 ;
     RECT  6.336 12.517 18.912 12.803 ;
     RECT  20.304 11.941 25.032 13.045 ;
     RECT  26.112 12.517 32.328 13.045 ;
     RECT  20.304 13.045 32.328 13.333 ;
     RECT  7.296 12.803 18.912 13.379 ;
     RECT  11.136 13.379 18.912 13.477 ;
     RECT  11.136 13.477 19.272 13.765 ;
     RECT  20.304 13.333 32.424 13.765 ;
     RECT  7.296 13.379 10.104 14.245 ;
     RECT  6.816 14.245 10.104 14.533 ;
     RECT  11.136 13.765 32.424 14.533 ;
     RECT  5.04 12.563 5.064 14.867 ;
     RECT  6.816 14.533 32.424 16.019 ;
     RECT  7.248 16.019 32.424 16.501 ;
     RECT  7.248 16.501 32.904 16.549 ;
     RECT  2.4 10.883 3 16.595 ;
     RECT  7.248 16.549 33.192 16.597 ;
     RECT  7.248 16.597 33.48 16.645 ;
     RECT  5.904 16.501 5.928 17.029 ;
     RECT  7.248 16.645 33.576 17.029 ;
     RECT  5.904 17.029 33.576 17.077 ;
     RECT  2.4 16.595 2.712 17.289 ;
     RECT  2.4 17.289 2.52 17.303 ;
     RECT  5.904 17.077 33.672 17.605 ;
     RECT  5.904 17.605 33.768 19.408 ;
  END
END dsfd_rly_283_SN
END LIBRARY
